(* Logix 5000 AddOnInstructionDefinition export Ed25519_SIGN; software revision 30.00; part 3 of 6 *)

ADD_ON_INSTRUCTION POINT_ENC   (* revision 1.0 20170916, vendor Kenneth A. Fischer *)
// Point Encode:
// Encode point (x,y) values into 32 8-bit pieces
// Requires POINT UDT
// Revision note:
// Rev1.0: 20170916 - Initial Release
VAR_IN_OUT
   Temp_C1 : DINT[22]; {required}
   Temp_C2 : DINT[22]; {required}
   Temp_C3 : DINT[22]; {required}
   Temp_C4 : DINT[22]; {required}   // U
   Temp_D : DINT[43]; {required}
   Temp_E : DINT[32]; {required}
   Inp_P : POINT; {required}
   Out_E : DINT[32]; {required}
END_VAR
VAR_OUTPUT
   i : INT; {access Read Only}
END_VAR
VAR_INPUT
   SEQCTRL_RESET : BOOL;   // Resets Point Multiplication if Toggled True
END_VAR
VAR_OUTPUT
   SEQCTRL_DN : BOOL; {access Read Only}   // Complete
   SEQCTRL_STEP : INT; {access Read Only}
END_VAR
VAR
   SEQCTRL_CMD : INT;
   SEQCTRL_DONE : INT;
   SEQCTRL_CMD_TABLE : INT[40];
   SEQCTRL_NEXT_STEP : INT;
   TEMP : INT;
   j : INT;
   b : DINT;
   B256_MUL : B256_MUL;
   B256_SQU : B256_SQU;
   B256_ADJ : B256_ADJ;
   B256_CtoE : B256_CtoE;
   D_SHL : D_SHL;
   TEMP1 : DINT;
   TEMP2 : DINT;
END_VAR

ROUTINE Logic   (* ladder *)
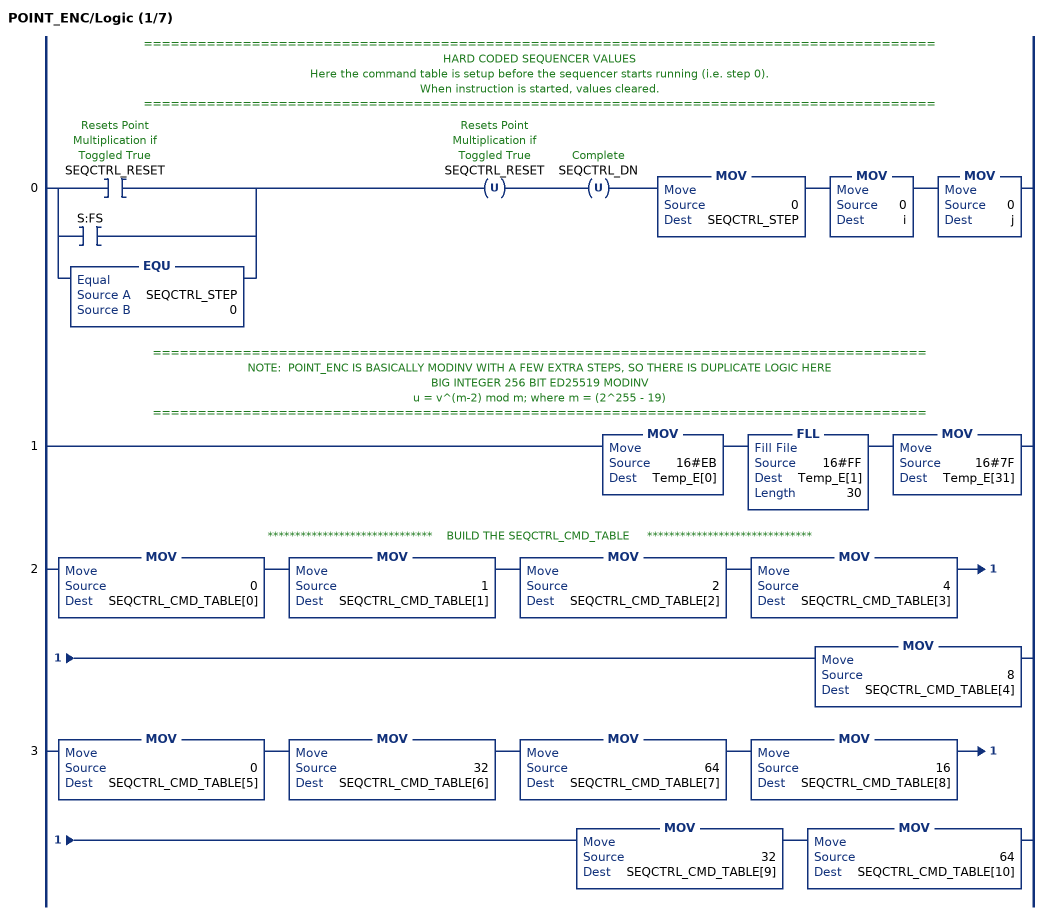
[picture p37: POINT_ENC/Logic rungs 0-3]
   // ========================================================================================
   // HARD CODED SEQUENCER VALUES
   // Here the command table is setup before the sequencer starts running (i.e. step 0).
   // When instruction is started, values cleared.
   // ========================================================================================
   0: [[XIC(SEQCTRL_RESET) ,XIC(S:FS) ] ,EQU(SEQCTRL_STEP,0) ]OTU(SEQCTRL_RESET)OTU(SEQCTRL_DN)MOV(0,SEQCTRL_STEP)MOV(0,i)MOV(0,j);
   // ======================================================================================
   // NOTE:  POINT_ENC IS BASICALLY MODINV WITH A FEW EXTRA STEPS, SO THERE IS DUPLICATE LOGIC HERE
   // BIG INTEGER 256 BIT ED25519 MODINV
   //  u = v^(m-2) mod m; where m = (2^255 - 19)
   // ======================================================================================
   1: MOV(16#EB,Temp_E[0])FLL(16#FF,Temp_E[1],30)MOV(16#7F,Temp_E[31]);
   // ******************************    BUILD THE SEQCTRL_CMD_TABLE     ******************************
   2: MOV(0,SEQCTRL_CMD_TABLE[0])MOV(1,SEQCTRL_CMD_TABLE[1])MOV(2,SEQCTRL_CMD_TABLE[2])MOV(4,SEQCTRL_CMD_TABLE[3])MOV(8,SEQCTRL_CMD_TABLE[4]);
   3: MOV(0,SEQCTRL_CMD_TABLE[5])MOV(32,SEQCTRL_CMD_TABLE[6])MOV(64,SEQCTRL_CMD_TABLE[7])MOV(16,SEQCTRL_CMD_TABLE[8])MOV(32,SEQCTRL_CMD_TABLE[9])MOV(64,SEQCTRL_CMD_TABLE[10]);
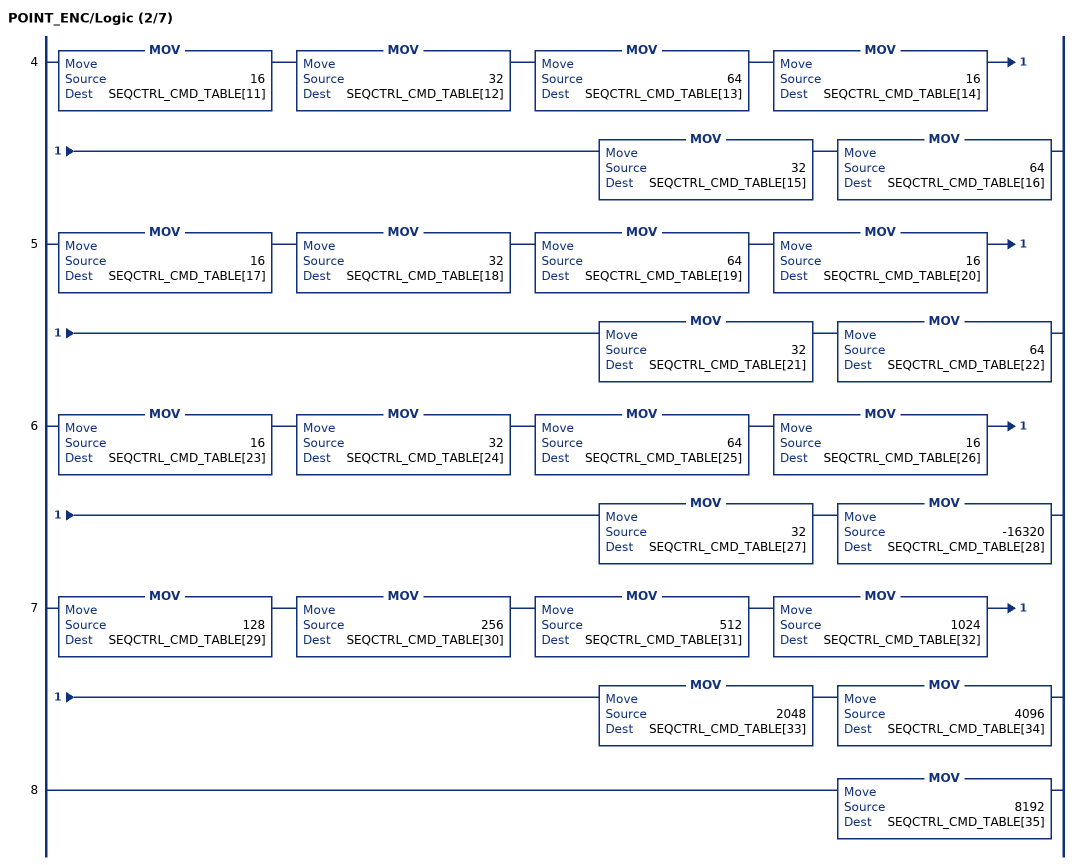
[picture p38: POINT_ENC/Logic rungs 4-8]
   4: MOV(16,SEQCTRL_CMD_TABLE[11])MOV(32,SEQCTRL_CMD_TABLE[12])MOV(64,SEQCTRL_CMD_TABLE[13])MOV(16,SEQCTRL_CMD_TABLE[14])MOV(32,SEQCTRL_CMD_TABLE[15])MOV(64,SEQCTRL_CMD_TABLE[16]);
   5: MOV(16,SEQCTRL_CMD_TABLE[17])MOV(32,SEQCTRL_CMD_TABLE[18])MOV(64,SEQCTRL_CMD_TABLE[19])MOV(16,SEQCTRL_CMD_TABLE[20])MOV(32,SEQCTRL_CMD_TABLE[21])MOV(64,SEQCTRL_CMD_TABLE[22]);
   6: MOV(16,SEQCTRL_CMD_TABLE[23])MOV(32,SEQCTRL_CMD_TABLE[24])MOV(64,SEQCTRL_CMD_TABLE[25])MOV(16,SEQCTRL_CMD_TABLE[26])MOV(32,SEQCTRL_CMD_TABLE[27])MOV(-16320,SEQCTRL_CMD_TABLE[28]);
   7: MOV(128,SEQCTRL_CMD_TABLE[29])MOV(256,SEQCTRL_CMD_TABLE[30])MOV(512,SEQCTRL_CMD_TABLE[31])MOV(1024,SEQCTRL_CMD_TABLE[32])MOV(2048,SEQCTRL_CMD_TABLE[33])MOV(4096,SEQCTRL_CMD_TABLE[34]);
   8: MOV(8192,SEQCTRL_CMD_TABLE[35]);
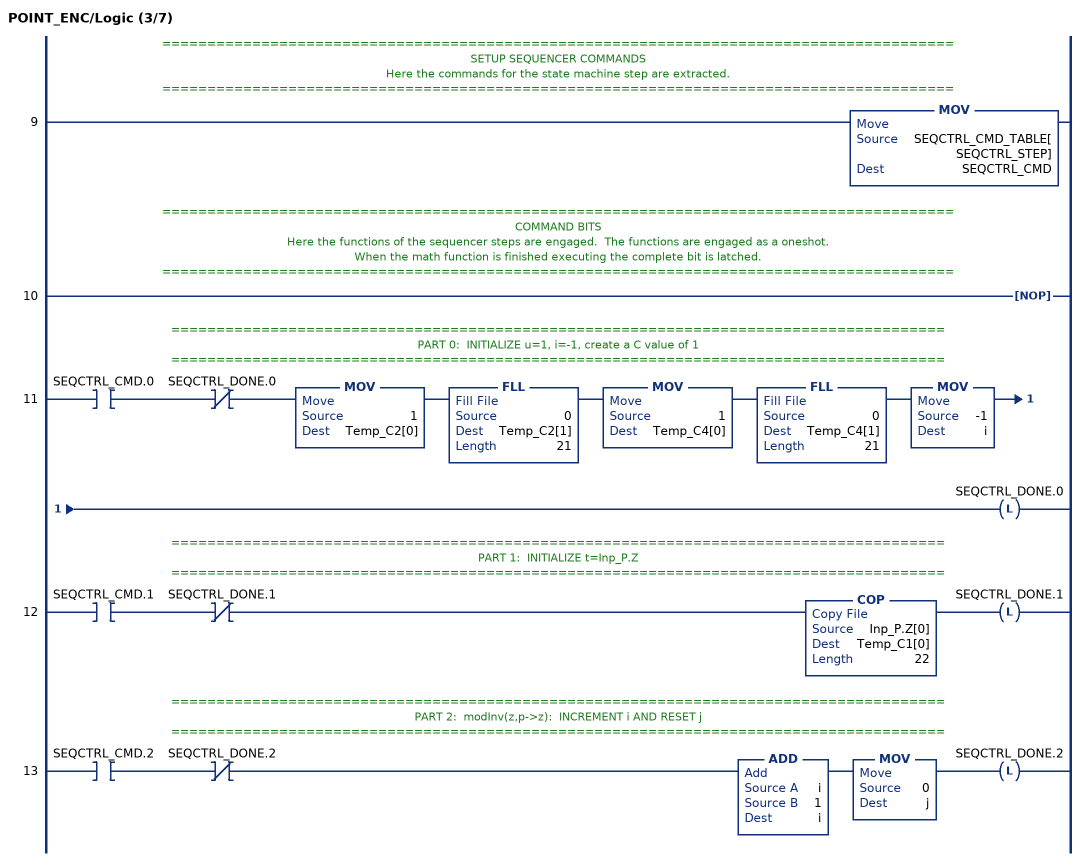
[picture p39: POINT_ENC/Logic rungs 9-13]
   // ========================================================================================
   // SETUP SEQUENCER COMMANDS
   // Here the commands for the state machine step are extracted.
   // ========================================================================================
   9: MOV(SEQCTRL_CMD_TABLE[SEQCTRL_STEP],SEQCTRL_CMD);
   // ========================================================================================
   // COMMAND BITS
   // Here the functions of the sequencer steps are engaged.  The functions are engaged as a oneshot.
   // When the math function is finished executing the complete bit is latched.
   // ========================================================================================
   10: NOP();
   // ======================================================================================
   // PART 0:  INITIALIZE u=1, i=-1, create a C value of 1
   // ======================================================================================
   11: XIC(SEQCTRL_CMD.0)XIO(SEQCTRL_DONE.0)MOV(1,Temp_C2[0])FLL(0,Temp_C2[1],21)MOV(1,Temp_C4[0])FLL(0,Temp_C4[1],21)MOV(-1,i)OTL(SEQCTRL_DONE.0);
   // ======================================================================================
   // PART 1:  INITIALIZE t=Inp_P.Z
   // ======================================================================================
   12: XIC(SEQCTRL_CMD.1)XIO(SEQCTRL_DONE.1)COP(Inp_P.Z[0],Temp_C1[0],22)OTL(SEQCTRL_DONE.1);
   // ======================================================================================
   // PART 2:  modInv(z,p->z):  INCREMENT i AND RESET j
   // ======================================================================================
   13: XIC(SEQCTRL_CMD.2)XIO(SEQCTRL_DONE.2)ADD(i,1,i)MOV(0,j)OTL(SEQCTRL_DONE.2);
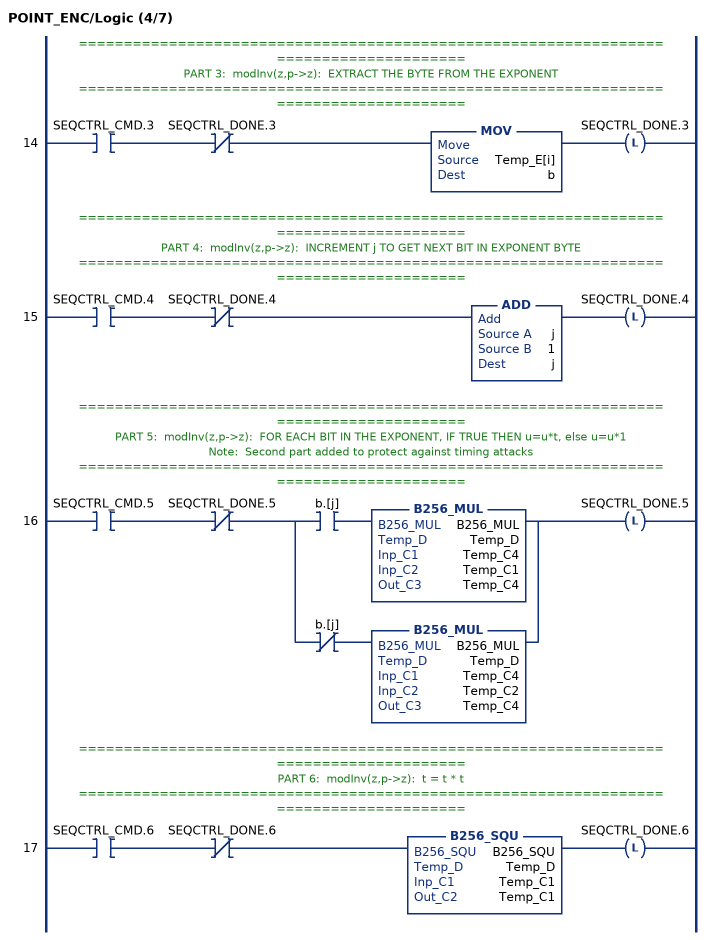
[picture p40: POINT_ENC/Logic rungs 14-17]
   // ======================================================================================
   // PART 3:  modInv(z,p->z):  EXTRACT THE BYTE FROM THE EXPONENT
   // ======================================================================================
   14: XIC(SEQCTRL_CMD.3)XIO(SEQCTRL_DONE.3)MOV(Temp_E[i],b)OTL(SEQCTRL_DONE.3);
   // ======================================================================================
   // PART 4:  modInv(z,p->z):  INCREMENT j TO GET NEXT BIT IN EXPONENT BYTE
   // ======================================================================================
   15: XIC(SEQCTRL_CMD.4)XIO(SEQCTRL_DONE.4)ADD(j,1,j)OTL(SEQCTRL_DONE.4);
   // ======================================================================================
   // PART 5:  modInv(z,p->z):  FOR EACH BIT IN THE EXPONENT, IF TRUE THEN u=u*t, else u=u*1
   // Note:  Second part added to protect against timing attacks
   // ======================================================================================
   16: XIC(SEQCTRL_CMD.5)XIO(SEQCTRL_DONE.5)[XIC(b.[j]) B256_MUL(B256_MUL,Temp_D,Temp_C4,Temp_C1,Temp_C4) ,XIO(b.[j]) B256_MUL(B256_MUL,Temp_D,Temp_C4,Temp_C2,Temp_C4) ]OTL(SEQCTRL_DONE.5);
   // ======================================================================================
   // PART 6:  modInv(z,p->z):  t = t * t
   // ======================================================================================
   17: XIC(SEQCTRL_CMD.6)XIO(SEQCTRL_DONE.6)B256_SQU(B256_SQU,Temp_D,Temp_C1,Temp_C1)OTL(SEQCTRL_DONE.6);
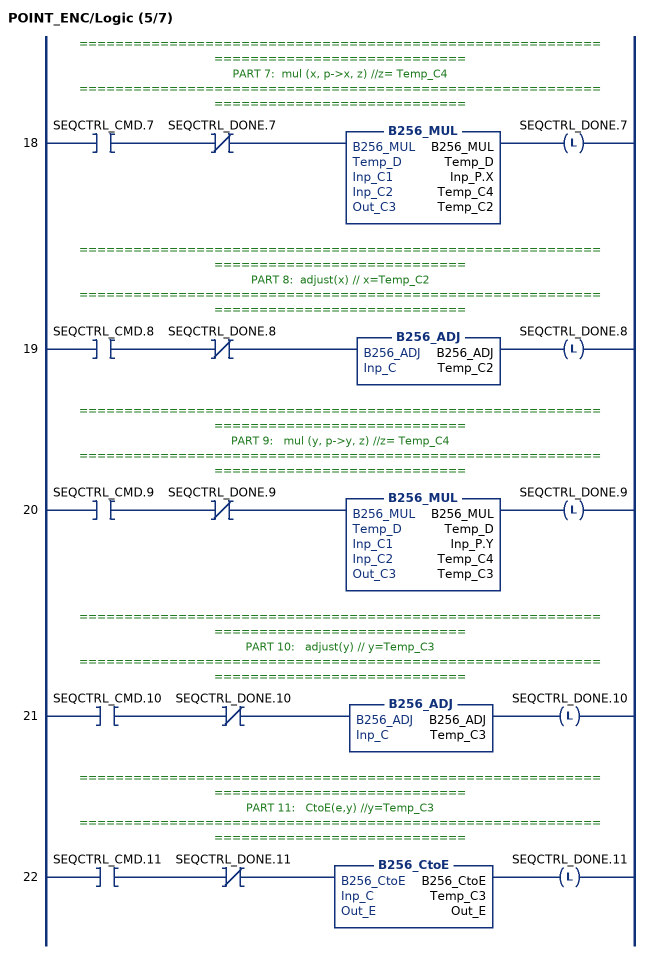
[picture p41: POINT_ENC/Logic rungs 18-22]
   // ======================================================================================
   // PART 7:  mul (x, p->x, z) //z= Temp_C4
   // ======================================================================================
   18: XIC(SEQCTRL_CMD.7)XIO(SEQCTRL_DONE.7)B256_MUL(B256_MUL,Temp_D,Inp_P.X,Temp_C4,Temp_C2)OTL(SEQCTRL_DONE.7);
   // ======================================================================================
   // PART 8:  adjust(x) // x=Temp_C2
   // ======================================================================================
   19: XIC(SEQCTRL_CMD.8)XIO(SEQCTRL_DONE.8)B256_ADJ(B256_ADJ,Temp_C2)OTL(SEQCTRL_DONE.8);
   // ======================================================================================
   // PART 9:   mul (y, p->y, z) //z= Temp_C4
   // ======================================================================================
   20: XIC(SEQCTRL_CMD.9)XIO(SEQCTRL_DONE.9)B256_MUL(B256_MUL,Temp_D,Inp_P.Y,Temp_C4,Temp_C3)OTL(SEQCTRL_DONE.9);
   // ======================================================================================
   // PART 10:   adjust(y) // y=Temp_C3
   // ======================================================================================
   21: XIC(SEQCTRL_CMD.10)XIO(SEQCTRL_DONE.10)B256_ADJ(B256_ADJ,Temp_C3)OTL(SEQCTRL_DONE.10);
   // ======================================================================================
   // PART 11:   CtoE(e,y) //y=Temp_C3
   // ======================================================================================
   22: XIC(SEQCTRL_CMD.11)XIO(SEQCTRL_DONE.11)B256_CtoE(B256_CtoE,Temp_C3,Out_E)OTL(SEQCTRL_DONE.11);
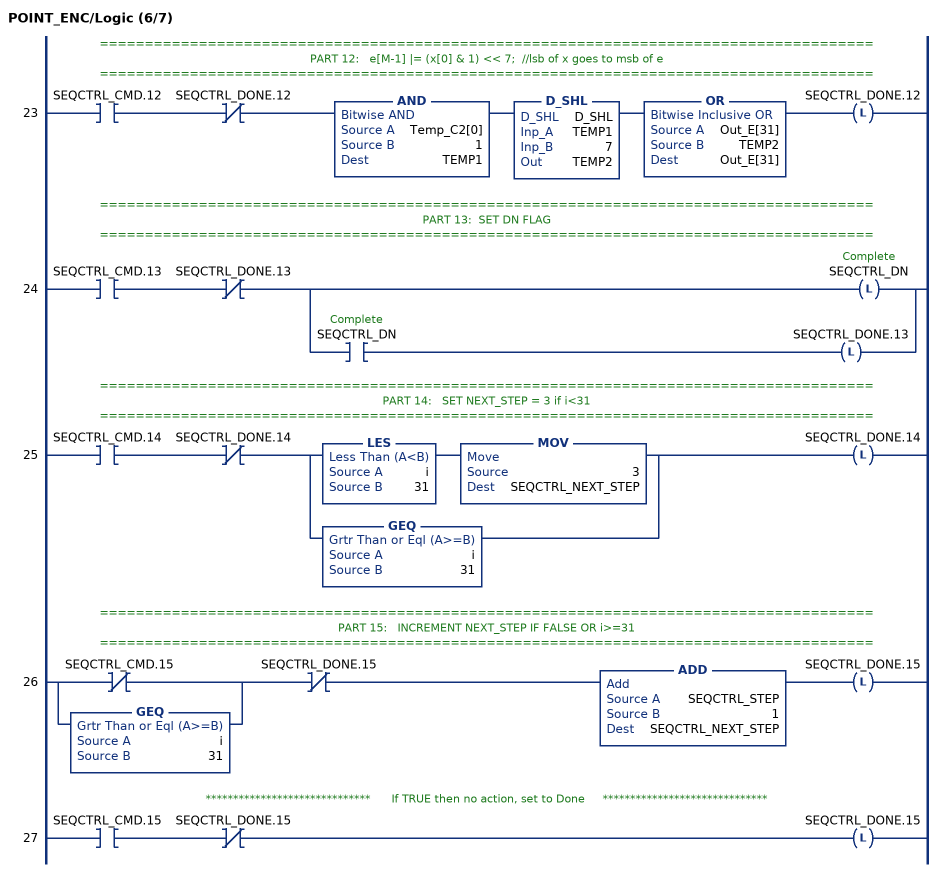
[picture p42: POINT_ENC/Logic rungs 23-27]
   // ======================================================================================
   // PART 12:   e[M-1] |= (x[0] & 1) << 7;  //lsb of x goes to msb of e
   // ======================================================================================
   23: XIC(SEQCTRL_CMD.12)XIO(SEQCTRL_DONE.12)AND(Temp_C2[0],1,TEMP1)D_SHL(D_SHL,TEMP1,7,TEMP2)OR(Out_E[31],TEMP2,Out_E[31])OTL(SEQCTRL_DONE.12);
   // ======================================================================================
   // PART 13:  SET DN FLAG
   // ======================================================================================
   24: XIC(SEQCTRL_CMD.13)XIO(SEQCTRL_DONE.13)[OTL(SEQCTRL_DN) ,XIC(SEQCTRL_DN) OTL(SEQCTRL_DONE.13) ];
   // ======================================================================================
   // PART 14:   SET NEXT_STEP = 3 if i<31
   // ======================================================================================
   25: XIC(SEQCTRL_CMD.14)XIO(SEQCTRL_DONE.14)[LES(i,31) MOV(3,SEQCTRL_NEXT_STEP) ,GEQ(i,31) ]OTL(SEQCTRL_DONE.14);
   // ======================================================================================
   // PART 15:   INCREMENT NEXT_STEP IF FALSE OR i>=31
   // ======================================================================================
   26: [XIO(SEQCTRL_CMD.15) ,GEQ(i,31) ]XIO(SEQCTRL_DONE.15)ADD(SEQCTRL_STEP,1,SEQCTRL_NEXT_STEP)OTL(SEQCTRL_DONE.15);
   // ******************************      If TRUE then no action, set to Done     ******************************
   27: XIC(SEQCTRL_CMD.15)XIO(SEQCTRL_DONE.15)OTL(SEQCTRL_DONE.15);
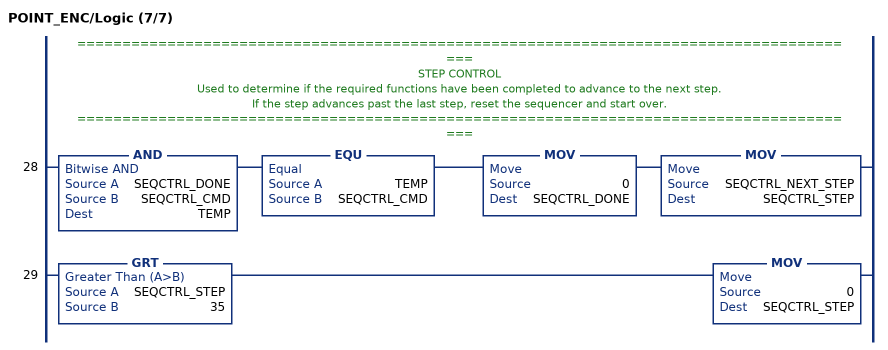
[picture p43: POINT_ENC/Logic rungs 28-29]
   // ========================================================================================
   // STEP CONTROL
   // Used to determine if the required functions have been completed to advance to the next step.
   // If the step advances past the last step, reset the sequencer and start over.
   // ========================================================================================
   28: AND(SEQCTRL_DONE,SEQCTRL_CMD,TEMP)EQU(TEMP,SEQCTRL_CMD)MOV(0,SEQCTRL_DONE)MOV(SEQCTRL_NEXT_STEP,SEQCTRL_STEP);
   29: GRT(SEQCTRL_STEP,35)MOV(0,SEQCTRL_STEP);
END_ROUTINE
END_ADD_ON_INSTRUCTION

ADD_ON_INSTRUCTION B256_MODL   (* revision 1.0 20170916, vendor Kenneth A. Fischer *)
// e = d mod L
// L is curve group order
// Revision note:
// Rev1.0: 20170916 - Initial Release
VAR_IN_OUT
   Temp_C : DINT[22]; {required}
   Temp_D : DINT[43]; {required}
   Inp_D : DINT[43]; {required}   // V
   Out_E : DINT[32]; {required}   // U
END_VAR
VAR_INPUT
   SEQCTRL_RESET : BOOL;   // Resets Mod_L if Toggled True
END_VAR
VAR_OUTPUT
   SEQCTRL_DN : BOOL; {access Read Only}   // Complete
   SEQCTRL_STEP : INT; {access Read Only}
   i : INT; {access Read Only}
END_VAR
VAR
   SEQCTRL_CMD : INT;
   SEQCTRL_DONE : INT;
   SEQCTRL_NEXT_STEP : INT;
   j : INT;
   SEQCTRL_CMD_TABLE : INT[100];
   k : INT;
   p : INT;
   t : DINT;
   carry : DINT;
   s : DINT;
   q : INT;
   TEMP : INT;
   L : DINT[22];
   TEMPDINT : DINT;
   D_SHR : D_SHR;
   negative : DINT;
   B256_CtoE : B256_CtoE;
END_VAR

ROUTINE Logic   (* ladder *)
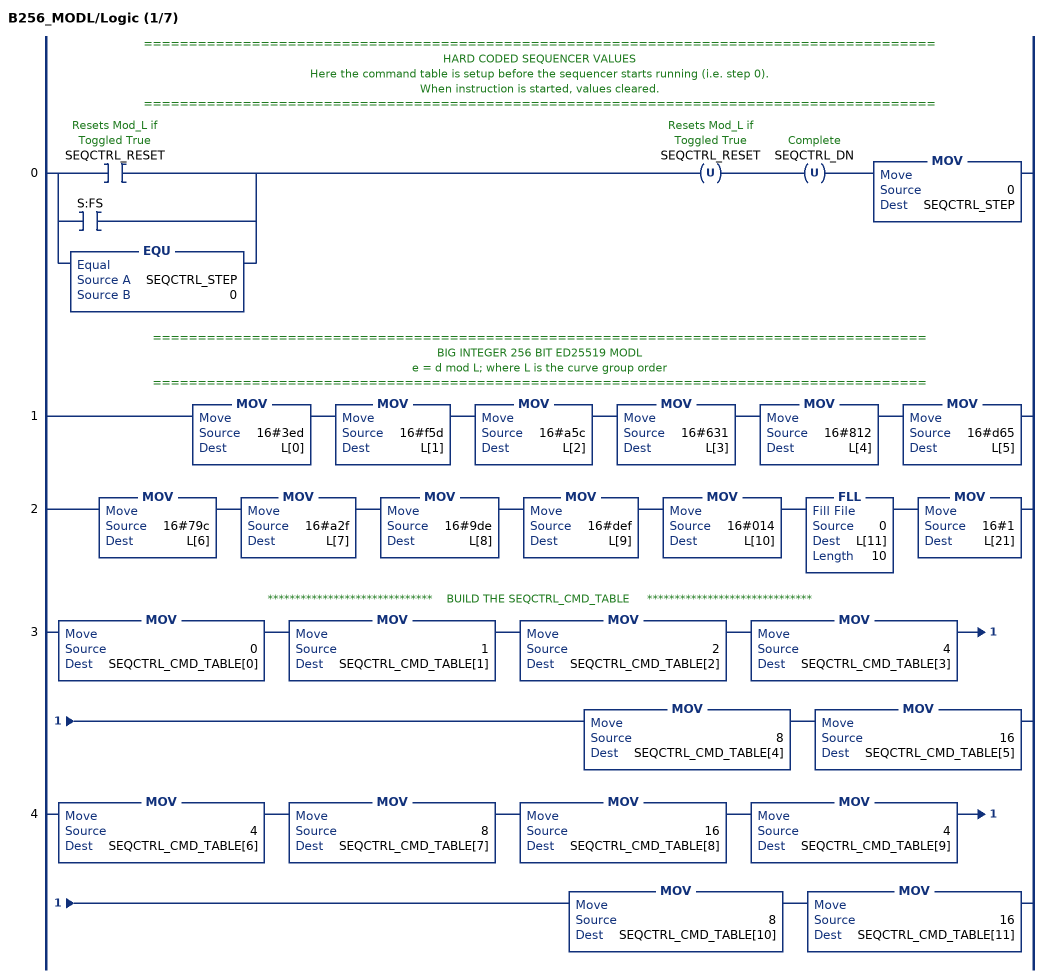
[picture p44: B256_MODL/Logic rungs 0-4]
   // ========================================================================================
   // HARD CODED SEQUENCER VALUES
   // Here the command table is setup before the sequencer starts running (i.e. step 0).
   // When instruction is started, values cleared.
   // ========================================================================================
   0: [[XIC(SEQCTRL_RESET) ,XIC(S:FS) ] ,EQU(SEQCTRL_STEP,0) ]OTU(SEQCTRL_RESET)OTU(SEQCTRL_DN)MOV(0,SEQCTRL_STEP);
   // ======================================================================================
   // BIG INTEGER 256 BIT ED25519 MODL
   //  e = d mod L; where L is the curve group order
   // ======================================================================================
   1: MOV(16#3ed,L[0])MOV(16#f5d,L[1])MOV(16#a5c,L[2])MOV(16#631,L[3])MOV(16#812,L[4])MOV(16#d65,L[5]);
   2: MOV(16#79c,L[6])MOV(16#a2f,L[7])MOV(16#9de,L[8])MOV(16#def,L[9])MOV(16#014,L[10])FLL(0,L[11],10)MOV(16#1,L[21]);
   // ******************************    BUILD THE SEQCTRL_CMD_TABLE     ******************************
   3: MOV(0,SEQCTRL_CMD_TABLE[0])MOV(1,SEQCTRL_CMD_TABLE[1])MOV(2,SEQCTRL_CMD_TABLE[2])MOV(4,SEQCTRL_CMD_TABLE[3])MOV(8,SEQCTRL_CMD_TABLE[4])MOV(16,SEQCTRL_CMD_TABLE[5]);
   4: MOV(4,SEQCTRL_CMD_TABLE[6])MOV(8,SEQCTRL_CMD_TABLE[7])MOV(16,SEQCTRL_CMD_TABLE[8])MOV(4,SEQCTRL_CMD_TABLE[9])MOV(8,SEQCTRL_CMD_TABLE[10])MOV(16,SEQCTRL_CMD_TABLE[11]);
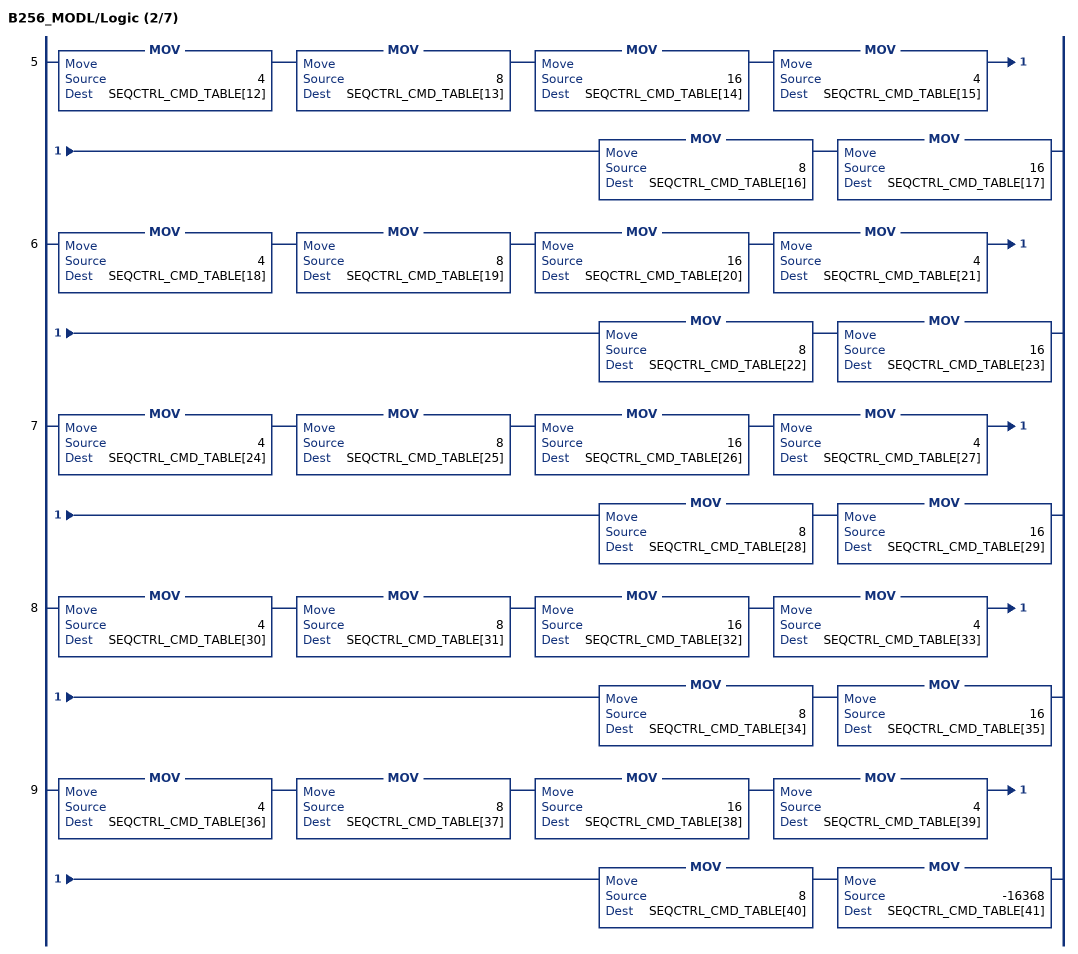
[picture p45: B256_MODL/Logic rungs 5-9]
   5: MOV(4,SEQCTRL_CMD_TABLE[12])MOV(8,SEQCTRL_CMD_TABLE[13])MOV(16,SEQCTRL_CMD_TABLE[14])MOV(4,SEQCTRL_CMD_TABLE[15])MOV(8,SEQCTRL_CMD_TABLE[16])MOV(16,SEQCTRL_CMD_TABLE[17]);
   6: MOV(4,SEQCTRL_CMD_TABLE[18])MOV(8,SEQCTRL_CMD_TABLE[19])MOV(16,SEQCTRL_CMD_TABLE[20])MOV(4,SEQCTRL_CMD_TABLE[21])MOV(8,SEQCTRL_CMD_TABLE[22])MOV(16,SEQCTRL_CMD_TABLE[23]);
   7: MOV(4,SEQCTRL_CMD_TABLE[24])MOV(8,SEQCTRL_CMD_TABLE[25])MOV(16,SEQCTRL_CMD_TABLE[26])MOV(4,SEQCTRL_CMD_TABLE[27])MOV(8,SEQCTRL_CMD_TABLE[28])MOV(16,SEQCTRL_CMD_TABLE[29]);
   8: MOV(4,SEQCTRL_CMD_TABLE[30])MOV(8,SEQCTRL_CMD_TABLE[31])MOV(16,SEQCTRL_CMD_TABLE[32])MOV(4,SEQCTRL_CMD_TABLE[33])MOV(8,SEQCTRL_CMD_TABLE[34])MOV(16,SEQCTRL_CMD_TABLE[35]);
   9: MOV(4,SEQCTRL_CMD_TABLE[36])MOV(8,SEQCTRL_CMD_TABLE[37])MOV(16,SEQCTRL_CMD_TABLE[38])MOV(4,SEQCTRL_CMD_TABLE[39])MOV(8,SEQCTRL_CMD_TABLE[40])MOV(-16368,SEQCTRL_CMD_TABLE[41]);
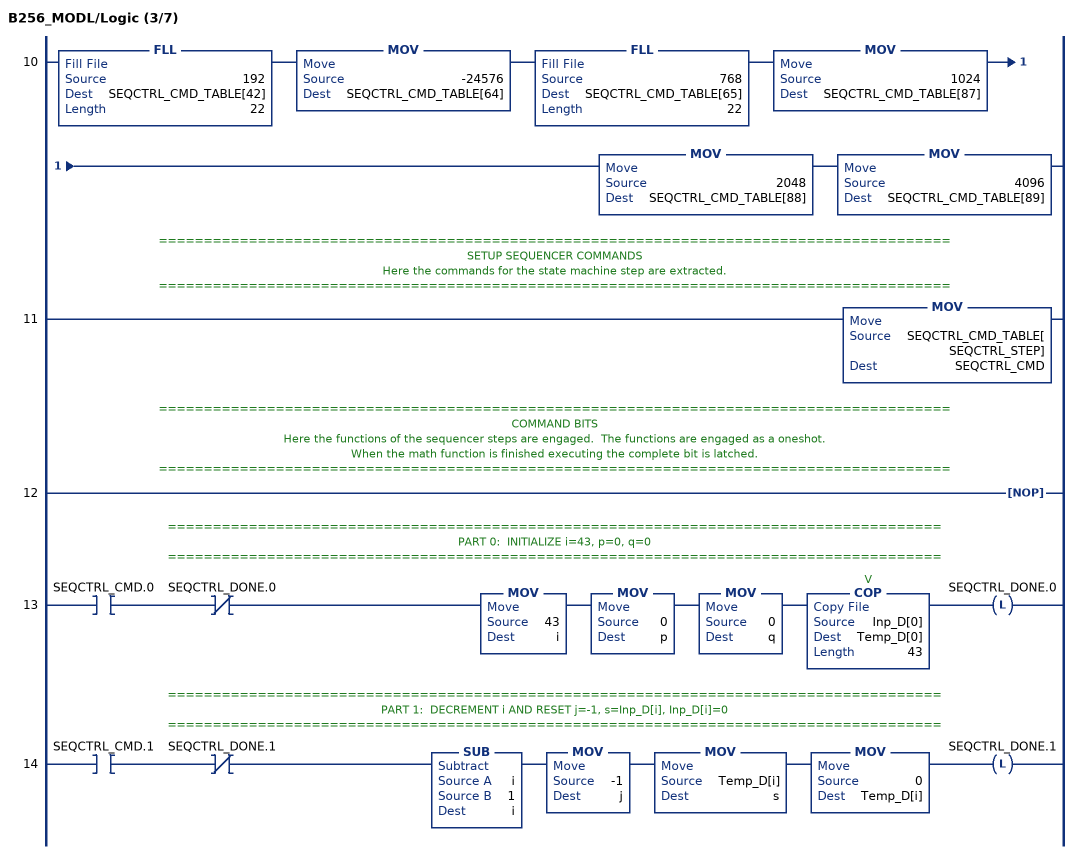
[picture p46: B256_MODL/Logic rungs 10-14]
   10: FLL(192,SEQCTRL_CMD_TABLE[42],22)MOV(-24576,SEQCTRL_CMD_TABLE[64])FLL(768,SEQCTRL_CMD_TABLE[65],22)MOV(1024,SEQCTRL_CMD_TABLE[87])MOV(2048,SEQCTRL_CMD_TABLE[88])MOV(4096,SEQCTRL_CMD_TABLE[89]);
   // ========================================================================================
   // SETUP SEQUENCER COMMANDS
   // Here the commands for the state machine step are extracted.
   // ========================================================================================
   11: MOV(SEQCTRL_CMD_TABLE[SEQCTRL_STEP],SEQCTRL_CMD);
   // ========================================================================================
   // COMMAND BITS
   // Here the functions of the sequencer steps are engaged.  The functions are engaged as a oneshot.
   // When the math function is finished executing the complete bit is latched.
   // ========================================================================================
   12: NOP();
   // ======================================================================================
   // PART 0:  INITIALIZE i=43, p=0, q=0
   // ======================================================================================
   13: XIC(SEQCTRL_CMD.0)XIO(SEQCTRL_DONE.0)MOV(43,i)MOV(0,p)MOV(0,q)COP(Inp_D[0],Temp_D[0],43)OTL(SEQCTRL_DONE.0);
   // ======================================================================================
   // PART 1:  DECREMENT i AND RESET j=-1, s=Inp_D[i], Inp_D[i]=0
   // ======================================================================================
   14: XIC(SEQCTRL_CMD.1)XIO(SEQCTRL_DONE.1)SUB(i,1,i)MOV(-1,j)MOV(Temp_D[i],s)MOV(0,Temp_D[i])OTL(SEQCTRL_DONE.1);
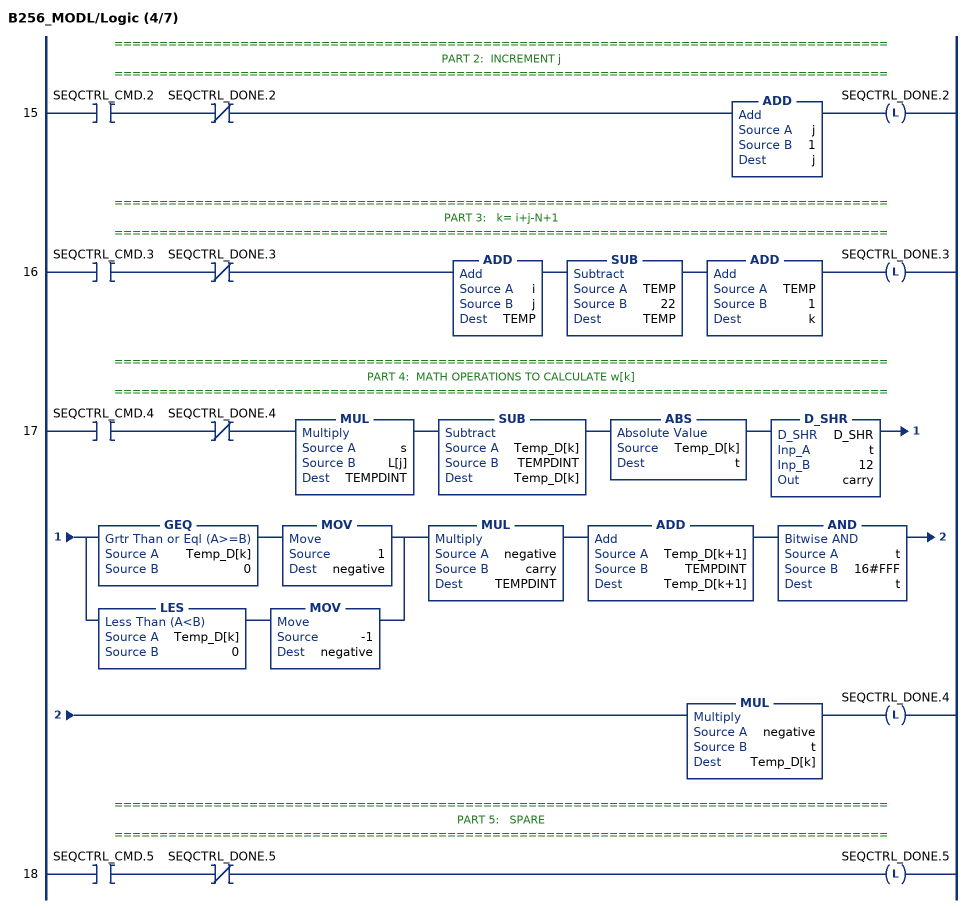
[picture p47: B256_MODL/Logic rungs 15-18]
   // ======================================================================================
   // PART 2:  INCREMENT j
   // ======================================================================================
   15: XIC(SEQCTRL_CMD.2)XIO(SEQCTRL_DONE.2)ADD(j,1,j)OTL(SEQCTRL_DONE.2);
   // ======================================================================================
   // PART 3:   k= i+j-N+1
   // ======================================================================================
   16: XIC(SEQCTRL_CMD.3)XIO(SEQCTRL_DONE.3)ADD(i,j,TEMP)SUB(TEMP,22,TEMP)ADD(TEMP,1,k)OTL(SEQCTRL_DONE.3);
   // ======================================================================================
   // PART 4:  MATH OPERATIONS TO CALCULATE w[k]
   // ======================================================================================
   17: XIC(SEQCTRL_CMD.4)XIO(SEQCTRL_DONE.4)MUL(s,L[j],TEMPDINT)SUB(Temp_D[k],TEMPDINT,Temp_D[k])ABS(Temp_D[k],t)D_SHR(D_SHR,t,12,carry)[GEQ(Temp_D[k],0) MOV(1,negative) ,LES(Temp_D[k],0) MOV(-1,negative) ]MUL(negative,carry,TEMPDINT)ADD(Temp_D[k+1],TEMPDINT,Temp_D[k+1])AND(t,16#FFF,t)MUL(negative,t,Temp_D[k])OTL(SEQCTRL_DONE.4);
   // ======================================================================================
   // PART 5:   SPARE
   // ======================================================================================
   18: XIC(SEQCTRL_CMD.5)XIO(SEQCTRL_DONE.5)OTL(SEQCTRL_DONE.5);
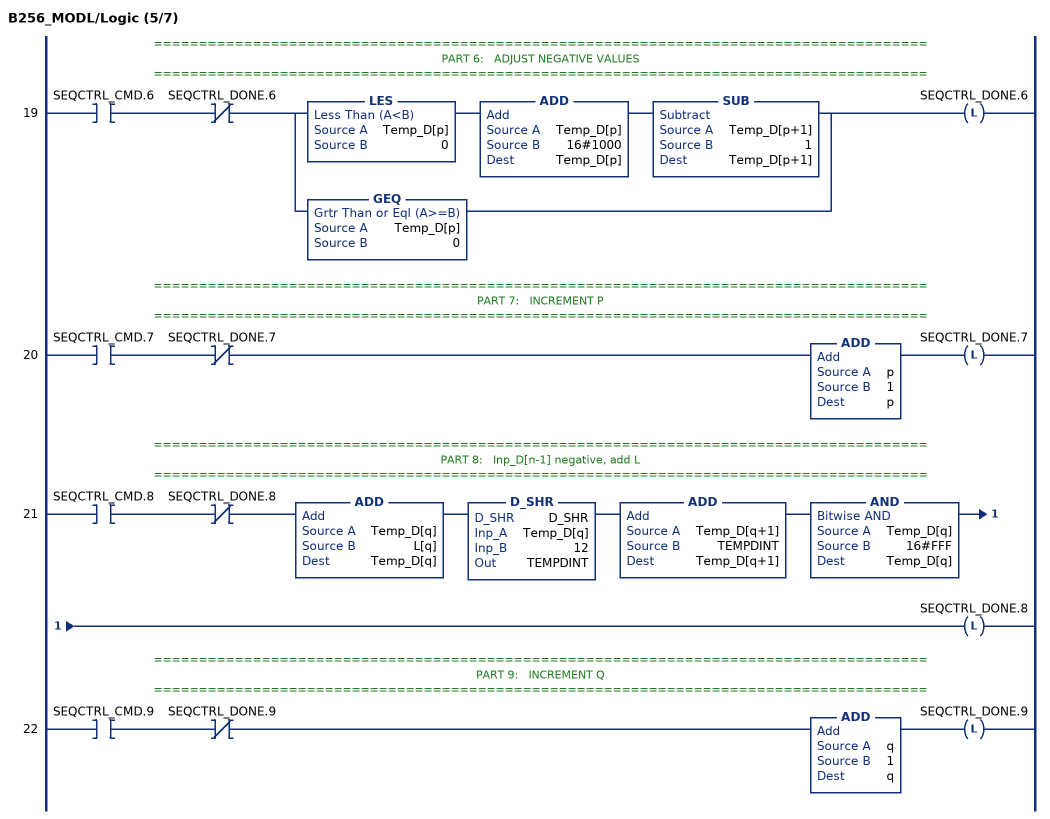
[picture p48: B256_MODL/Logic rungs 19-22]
   // ======================================================================================
   // PART 6:   ADJUST NEGATIVE VALUES
   // ======================================================================================
   19: XIC(SEQCTRL_CMD.6)XIO(SEQCTRL_DONE.6)[LES(Temp_D[p],0) ADD(Temp_D[p],16#1000,Temp_D[p]) SUB(Temp_D[p+1],1,Temp_D[p+1]) ,GEQ(Temp_D[p],0) ]OTL(SEQCTRL_DONE.6);
   // ======================================================================================
   // PART 7:   INCREMENT P
   // ======================================================================================
   20: XIC(SEQCTRL_CMD.7)XIO(SEQCTRL_DONE.7)ADD(p,1,p)OTL(SEQCTRL_DONE.7);
   // ======================================================================================
   // PART 8:   Inp_D[n-1] negative, add L
   // ======================================================================================
   21: XIC(SEQCTRL_CMD.8)XIO(SEQCTRL_DONE.8)ADD(Temp_D[q],L[q],Temp_D[q])D_SHR(D_SHR,Temp_D[q],12,TEMPDINT)ADD(Temp_D[q+1],TEMPDINT,Temp_D[q+1])AND(Temp_D[q],16#FFF,Temp_D[q])OTL(SEQCTRL_DONE.8);
   // ======================================================================================
   // PART 9:   INCREMENT Q
   // ======================================================================================
   22: XIC(SEQCTRL_CMD.9)XIO(SEQCTRL_DONE.9)ADD(q,1,q)OTL(SEQCTRL_DONE.9);
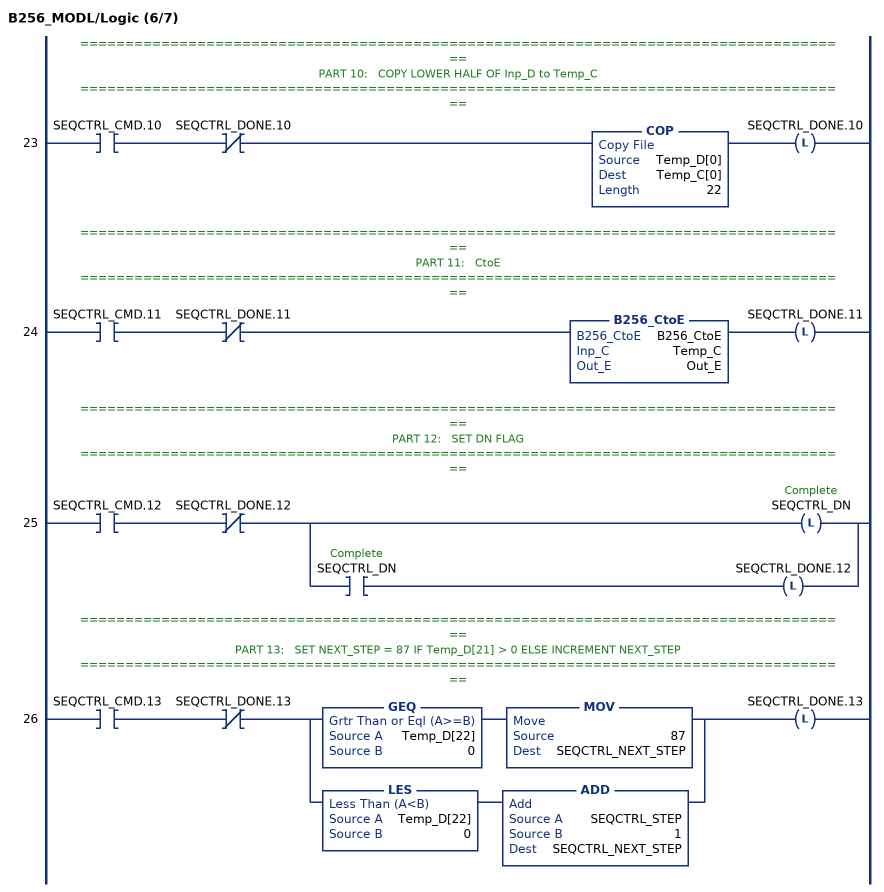
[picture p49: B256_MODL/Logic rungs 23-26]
   // ======================================================================================
   // PART 10:   COPY LOWER HALF OF Inp_D to Temp_C
   // ======================================================================================
   23: XIC(SEQCTRL_CMD.10)XIO(SEQCTRL_DONE.10)COP(Temp_D[0],Temp_C[0],22)OTL(SEQCTRL_DONE.10);
   // ======================================================================================
   // PART 11:   CtoE
   // ======================================================================================
   24: XIC(SEQCTRL_CMD.11)XIO(SEQCTRL_DONE.11)B256_CtoE(B256_CtoE,Temp_C,Out_E)OTL(SEQCTRL_DONE.11);
   // ======================================================================================
   // PART 12:   SET DN FLAG
   // ======================================================================================
   25: XIC(SEQCTRL_CMD.12)XIO(SEQCTRL_DONE.12)[OTL(SEQCTRL_DN) ,XIC(SEQCTRL_DN) OTL(SEQCTRL_DONE.12) ];
   // ======================================================================================
   // PART 13:   SET NEXT_STEP = 87 IF Temp_D[21] > 0 ELSE INCREMENT NEXT_STEP
   // ======================================================================================
   26: XIC(SEQCTRL_CMD.13)XIO(SEQCTRL_DONE.13)[GEQ(Temp_D[22],0) MOV(87,SEQCTRL_NEXT_STEP) ,LES(Temp_D[22],0) ADD(SEQCTRL_STEP,1,SEQCTRL_NEXT_STEP) ]OTL(SEQCTRL_DONE.13);
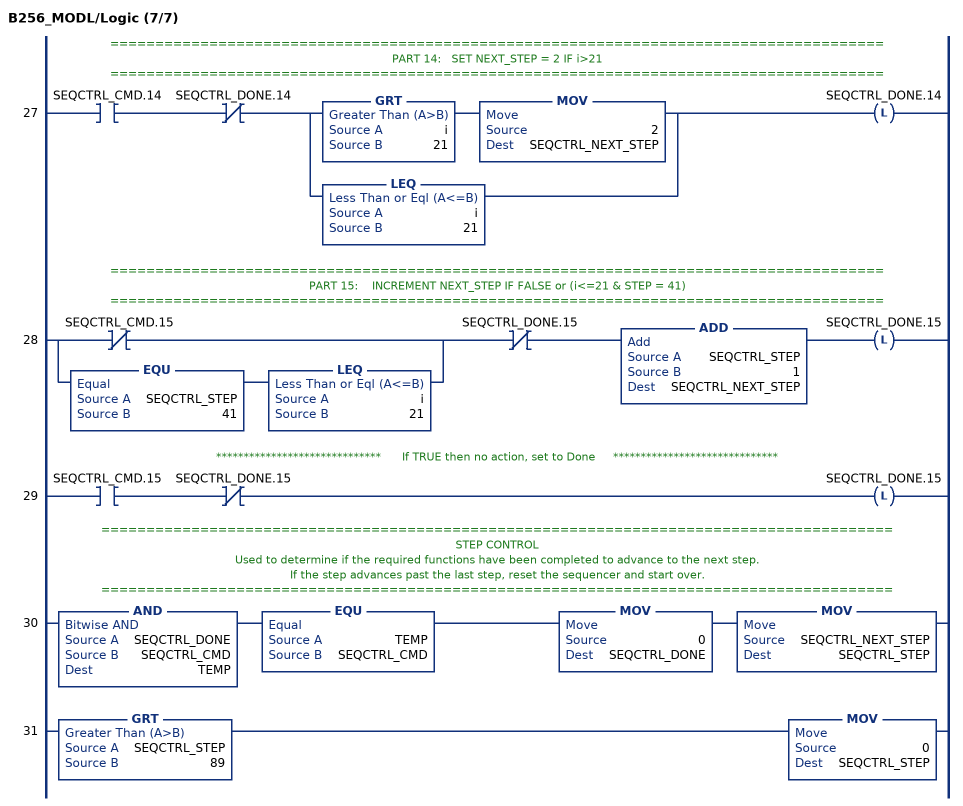
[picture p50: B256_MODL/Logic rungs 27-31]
   // ======================================================================================
   // PART 14:   SET NEXT_STEP = 2 IF i>21
   // ======================================================================================
   27: XIC(SEQCTRL_CMD.14)XIO(SEQCTRL_DONE.14)[GRT(i,21) MOV(2,SEQCTRL_NEXT_STEP) ,LEQ(i,21) ]OTL(SEQCTRL_DONE.14);
   // ======================================================================================
   // PART 15:    INCREMENT NEXT_STEP IF FALSE or (i<=21 & STEP = 41)
   // ======================================================================================
   28: [XIO(SEQCTRL_CMD.15) ,EQU(SEQCTRL_STEP,41) LEQ(i,21) ]XIO(SEQCTRL_DONE.15)ADD(SEQCTRL_STEP,1,SEQCTRL_NEXT_STEP)OTL(SEQCTRL_DONE.15);
   // ******************************      If TRUE then no action, set to Done     ******************************
   29: XIC(SEQCTRL_CMD.15)XIO(SEQCTRL_DONE.15)OTL(SEQCTRL_DONE.15);
   // ========================================================================================
   // STEP CONTROL
   // Used to determine if the required functions have been completed to advance to the next step.
   // If the step advances past the last step, reset the sequencer and start over.
   // ========================================================================================
   30: AND(SEQCTRL_DONE,SEQCTRL_CMD,TEMP)EQU(TEMP,SEQCTRL_CMD)MOV(0,SEQCTRL_DONE)MOV(SEQCTRL_NEXT_STEP,SEQCTRL_STEP);
   31: GRT(SEQCTRL_STEP,89)MOV(0,SEQCTRL_STEP);
END_ROUTINE
END_ADD_ON_INSTRUCTION

ADD_ON_INSTRUCTION B256_CtoS   (* revision 1.0 20170916, vendor Kenneth A. Fischer *)
// Convert 256-bit value using 22 12-bit pieces into 64 hex big endian string characters
// Revision note:
// Rev1.0: 20170916 - Initial Release
VAR_IN_OUT
   Inp_C : DINT[22]; {required}
   Out_S : STRING; {required}
END_VAR
VAR
   byte : DINT[3];
   i : INT;
   j : INT;
   k : DINT;
   D_SHR : D_SHR;
END_VAR

ROUTINE Logic   (* ladder *)
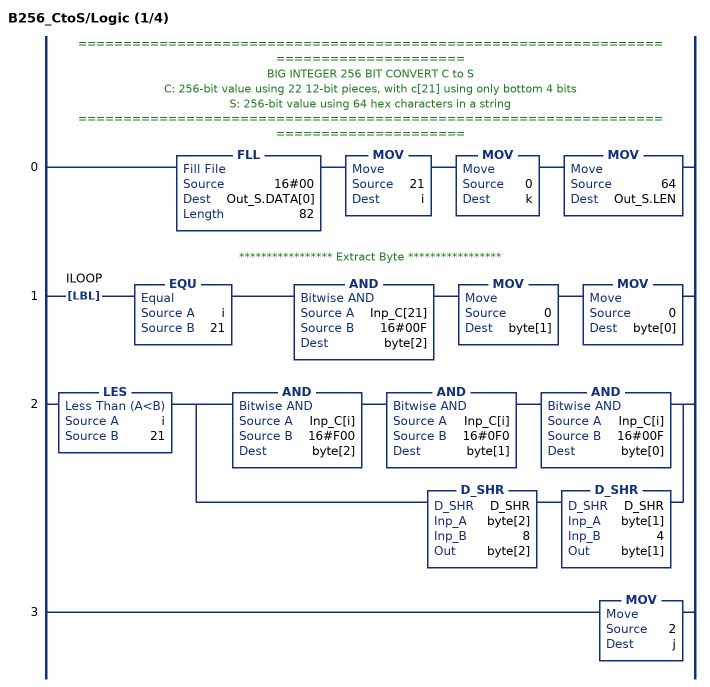
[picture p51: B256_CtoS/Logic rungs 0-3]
   // ======================================================================================
   // BIG INTEGER 256 BIT CONVERT C to S
   // C: 256-bit value using 22 12-bit pieces, with c[21] using only bottom 4 bits
   // S: 256-bit value using 64 hex characters in a string
   // ======================================================================================
   0: FLL(16#00,Out_S.DATA[0],82)MOV(21,i)MOV(0,k)MOV(64,Out_S.LEN);
   // ***************** Extract Byte *****************
   1: LBL(ILOOP)EQU(i,21)AND(Inp_C[21],16#00F,byte[2])MOV(0,byte[1])MOV(0,byte[0]);
   2: LES(i,21)[AND(Inp_C[i],16#F00,byte[2]) AND(Inp_C[i],16#0F0,byte[1]) AND(Inp_C[i],16#00F,byte[0]) ,D_SHR(D_SHR,byte[2],8,byte[2]) D_SHR(D_SHR,byte[1],4,byte[1]) ];
   3: MOV(2,j);
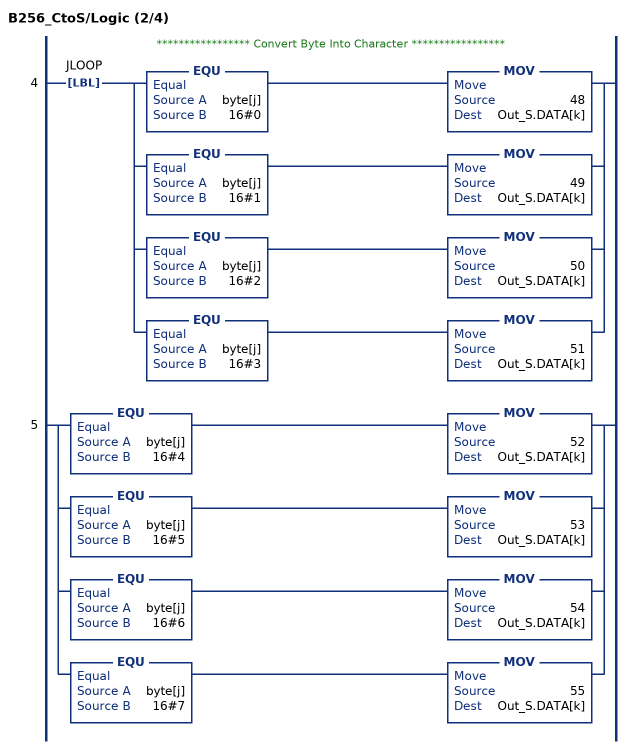
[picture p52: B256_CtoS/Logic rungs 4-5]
   // ***************** Convert Byte Into Character *****************
   4: LBL(JLOOP)[EQU(byte[j],16#0) MOV(48,Out_S.DATA[k]) ,EQU(byte[j],16#1) MOV(49,Out_S.DATA[k]) ,EQU(byte[j],16#2) MOV(50,Out_S.DATA[k]) ,EQU(byte[j],16#3) MOV(51,Out_S.DATA[k]) ];
   5: [EQU(byte[j],16#4) MOV(52,Out_S.DATA[k]) ,EQU(byte[j],16#5) MOV(53,Out_S.DATA[k]) ,EQU(byte[j],16#6) MOV(54,Out_S.DATA[k]) ,EQU(byte[j],16#7) MOV(55,Out_S.DATA[k]) ];
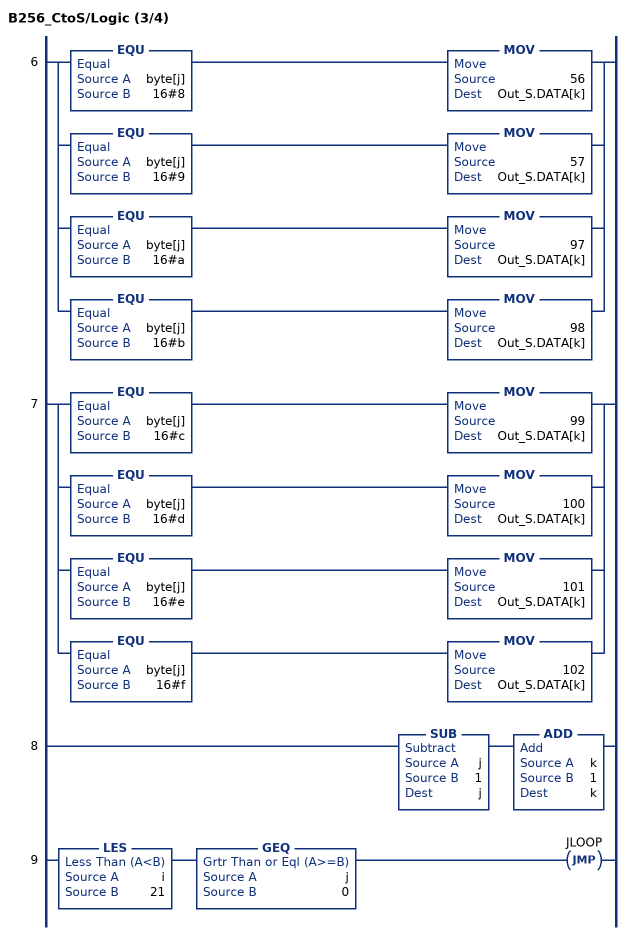
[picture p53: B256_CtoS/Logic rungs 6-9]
   6: [EQU(byte[j],16#8) MOV(56,Out_S.DATA[k]) ,EQU(byte[j],16#9) MOV(57,Out_S.DATA[k]) ,EQU(byte[j],16#a) MOV(97,Out_S.DATA[k]) ,EQU(byte[j],16#b) MOV(98,Out_S.DATA[k]) ];
   7: [EQU(byte[j],16#c) MOV(99,Out_S.DATA[k]) ,EQU(byte[j],16#d) MOV(100,Out_S.DATA[k]) ,EQU(byte[j],16#e) MOV(101,Out_S.DATA[k]) ,EQU(byte[j],16#f) MOV(102,Out_S.DATA[k]) ];
   8: SUB(j,1,j)ADD(k,1,k);
   9: LES(i,21)GEQ(j,0)JMP(JLOOP);
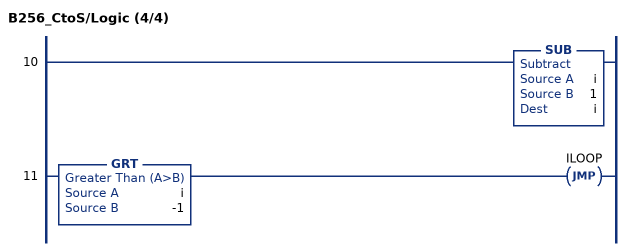
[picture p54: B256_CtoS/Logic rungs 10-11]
   10: SUB(i,1,i);
   11: GRT(i,-1)JMP(ILOOP);
END_ROUTINE
END_ADD_ON_INSTRUCTION
(* Logix 5000 AddOnInstructionDefinition export Ed25519_SIGN; software revision 30.00; part 4 of 6 *)

ADD_ON_INSTRUCTION B256_EtoC   (* revision 1.0 20170916, vendor Kenneth A. Fischer *)
// Convert 256-bit value using 32 8-bit pieces into 256-bit value using 22 12-bit pieces
// Revision note:
// Rev1.0: 20170916 - Initial Release
VAR_IN_OUT
   Inp_E : DINT[32]; {required}
   Out_C : DINT[22]; {required}
END_VAR
VAR
   i : INT;
   j : INT;
   TEMP1 : DINT;
   TEMP2 : DINT;
   D_SHL : D_SHL;
   D_SHR : D_SHR;
END_VAR

ROUTINE Logic   (* ladder *)
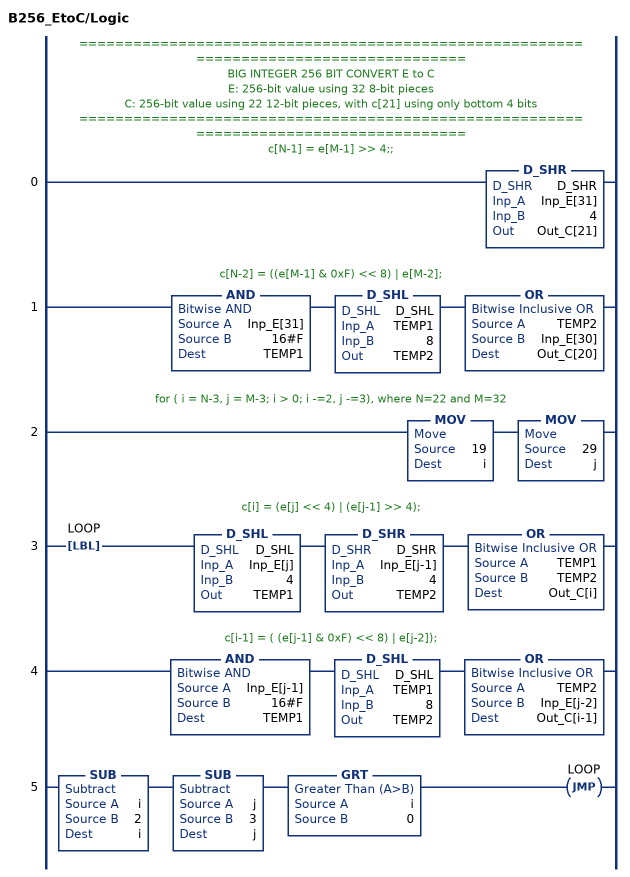
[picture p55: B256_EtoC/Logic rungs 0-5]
   // ======================================================================================
   // BIG INTEGER 256 BIT CONVERT E to C
   // E: 256-bit value using 32 8-bit pieces
   // C: 256-bit value using 22 12-bit pieces, with c[21] using only bottom 4 bits
   // ======================================================================================
   // c[N-1] = e[M-1] >> 4;;
   0: D_SHR(D_SHR,Inp_E[31],4,Out_C[21]);
   // c[N-2] = ((e[M-1] & 0xF) << 8) | e[M-2];
   1: AND(Inp_E[31],16#F,TEMP1)D_SHL(D_SHL,TEMP1,8,TEMP2)OR(TEMP2,Inp_E[30],Out_C[20]);
   // for ( i = N-3, j = M-3; i > 0; i -=2, j -=3), where N=22 and M=32
   2: MOV(19,i)MOV(29,j);
   // c[i] = (e[j] << 4) | (e[j-1] >> 4);
   3: LBL(LOOP)D_SHL(D_SHL,Inp_E[j],4,TEMP1)D_SHR(D_SHR,Inp_E[j-1],4,TEMP2)OR(TEMP1,TEMP2,Out_C[i]);
   // c[i-1] = ( (e[j-1] & 0xF) << 8) | e[j-2]);
   4: AND(Inp_E[j-1],16#F,TEMP1)D_SHL(D_SHL,TEMP1,8,TEMP2)OR(TEMP2,Inp_E[j-2],Out_C[i-1]);
   5: SUB(i,2,i)SUB(j,3,j)GRT(i,0)JMP(LOOP);
END_ROUTINE
END_ADD_ON_INSTRUCTION

ADD_ON_INSTRUCTION B256_EtoL   (* revision 1.0 20170916, vendor Kenneth A. Fischer *)
// Convert 256-bit value using 32 8-bit pieces into 256-bit value using 4 64-bit pieces
// Revision note:
// Rev1.0: 20170916 - Initial Release
VAR_IN_OUT
   Inp_E : DINT[32]; {required}
   Out_L : LINT[4]; {required}
END_VAR
VAR
   D_SHL : D_SHL;
   Wrk_Out : DINT[2];
   i : INT;
   j : INT;
   TEMP : DINT;
END_VAR

ROUTINE Logic   (* ladder *)
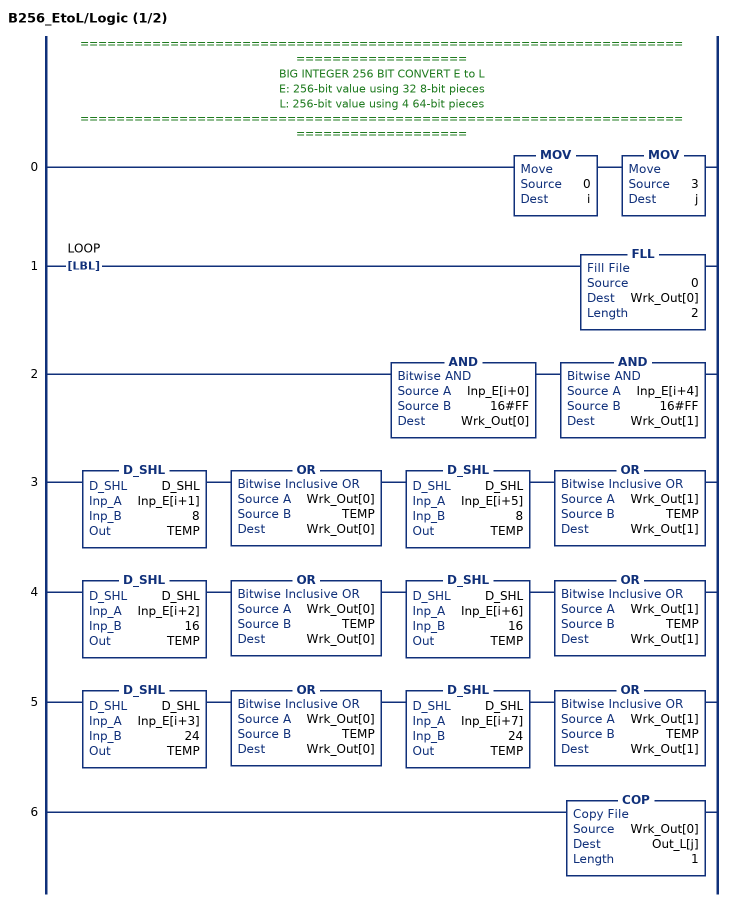
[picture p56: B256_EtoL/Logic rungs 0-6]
   // ======================================================================================
   // BIG INTEGER 256 BIT CONVERT E to L
   // E: 256-bit value using 32 8-bit pieces
   // L: 256-bit value using 4 64-bit pieces
   // ======================================================================================
   0: MOV(0,i)MOV(3,j);
   1: LBL(LOOP)FLL(0,Wrk_Out[0],2);
   2: AND(Inp_E[i+0],16#FF,Wrk_Out[0])AND(Inp_E[i+4],16#FF,Wrk_Out[1]);
   3: D_SHL(D_SHL,Inp_E[i+1],8,TEMP)OR(Wrk_Out[0],TEMP,Wrk_Out[0])D_SHL(D_SHL,Inp_E[i+5],8,TEMP)OR(Wrk_Out[1],TEMP,Wrk_Out[1]);
   4: D_SHL(D_SHL,Inp_E[i+2],16,TEMP)OR(Wrk_Out[0],TEMP,Wrk_Out[0])D_SHL(D_SHL,Inp_E[i+6],16,TEMP)OR(Wrk_Out[1],TEMP,Wrk_Out[1]);
   5: D_SHL(D_SHL,Inp_E[i+3],24,TEMP)OR(Wrk_Out[0],TEMP,Wrk_Out[0])D_SHL(D_SHL,Inp_E[i+7],24,TEMP)OR(Wrk_Out[1],TEMP,Wrk_Out[1]);
   6: COP(Wrk_Out[0],Out_L[j],1);
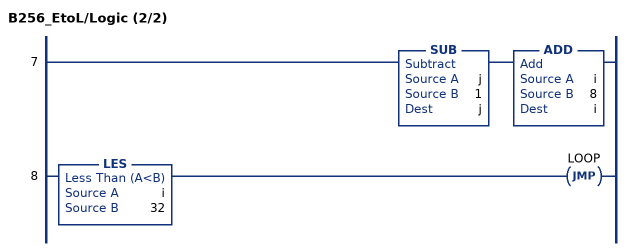
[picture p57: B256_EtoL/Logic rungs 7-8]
   7: SUB(j,1,j)ADD(i,8,i);
   8: LES(i,32)JMP(LOOP);
END_ROUTINE
END_ADD_ON_INSTRUCTION

ADD_ON_INSTRUCTION B256_StoC   (* revision 1.0 20170916, vendor Kenneth A. Fischer *)
// Convert 256-bit value using 64 hex string characters into 256-bit value using 22 12-bit pieces
// Revision note:
// Rev1.0: 20170916 - Initial Release
VAR_IN_OUT
   Inp_S : STRING; {required}
   Out_C : DINT[22]; {required}
END_VAR
VAR
   byte : DINT[3];
   D_SHL : D_SHL;
   i : INT;
   j : INT;
   k : DINT;
   temp : DINT;
END_VAR

ROUTINE Logic   (* ladder *)
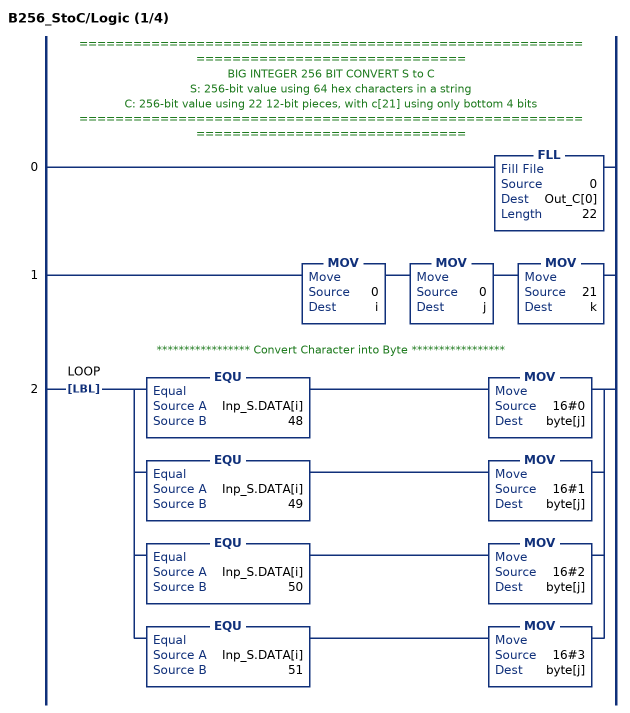
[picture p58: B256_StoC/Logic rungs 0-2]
   // ======================================================================================
   // BIG INTEGER 256 BIT CONVERT S to C
   // S: 256-bit value using 64 hex characters in a string
   // C: 256-bit value using 22 12-bit pieces, with c[21] using only bottom 4 bits
   // ======================================================================================
   0: FLL(0,Out_C[0],22);
   1: MOV(0,i)MOV(0,j)MOV(21,k);
   // ***************** Convert Character into Byte *****************
   2: LBL(LOOP)[EQU(Inp_S.DATA[i],48) MOV(16#0,byte[j]) ,EQU(Inp_S.DATA[i],49) MOV(16#1,byte[j]) ,EQU(Inp_S.DATA[i],50) MOV(16#2,byte[j]) ,EQU(Inp_S.DATA[i],51) MOV(16#3,byte[j]) ];
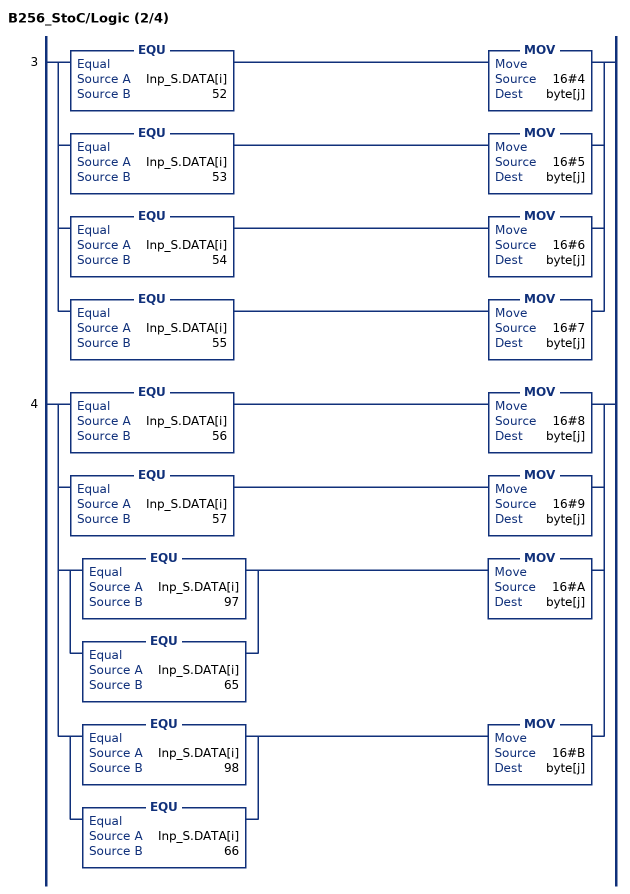
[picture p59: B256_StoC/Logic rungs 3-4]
   3: [EQU(Inp_S.DATA[i],52) MOV(16#4,byte[j]) ,EQU(Inp_S.DATA[i],53) MOV(16#5,byte[j]) ,EQU(Inp_S.DATA[i],54) MOV(16#6,byte[j]) ,EQU(Inp_S.DATA[i],55) MOV(16#7,byte[j]) ];
   4: [EQU(Inp_S.DATA[i],56) MOV(16#8,byte[j]) ,EQU(Inp_S.DATA[i],57) MOV(16#9,byte[j]) ,[EQU(Inp_S.DATA[i],97) ,EQU(Inp_S.DATA[i],65) ] MOV(16#A,byte[j]) ,[EQU(Inp_S.DATA[i],98) ,EQU(Inp_S.DATA[i],66) ] MOV(16#B,byte[j]) ];
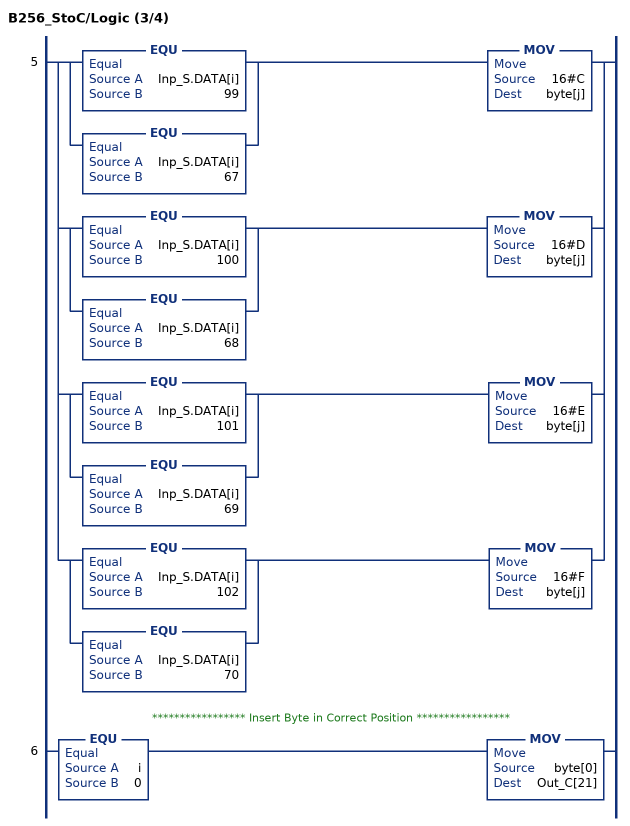
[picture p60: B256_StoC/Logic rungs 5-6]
   5: [[EQU(Inp_S.DATA[i],99) ,EQU(Inp_S.DATA[i],67) ] MOV(16#C,byte[j]) ,[EQU(Inp_S.DATA[i],100) ,EQU(Inp_S.DATA[i],68) ] MOV(16#D,byte[j]) ,[EQU(Inp_S.DATA[i],101) ,EQU(Inp_S.DATA[i],69) ] MOV(16#E,byte[j]) ,[EQU(Inp_S.DATA[i],102) ,EQU(Inp_S.DATA[i],70) ] MOV(16#F,byte[j]) ];
   // ***************** Insert Byte in Correct Position *****************
   6: EQU(i,0)MOV(byte[0],Out_C[21]);
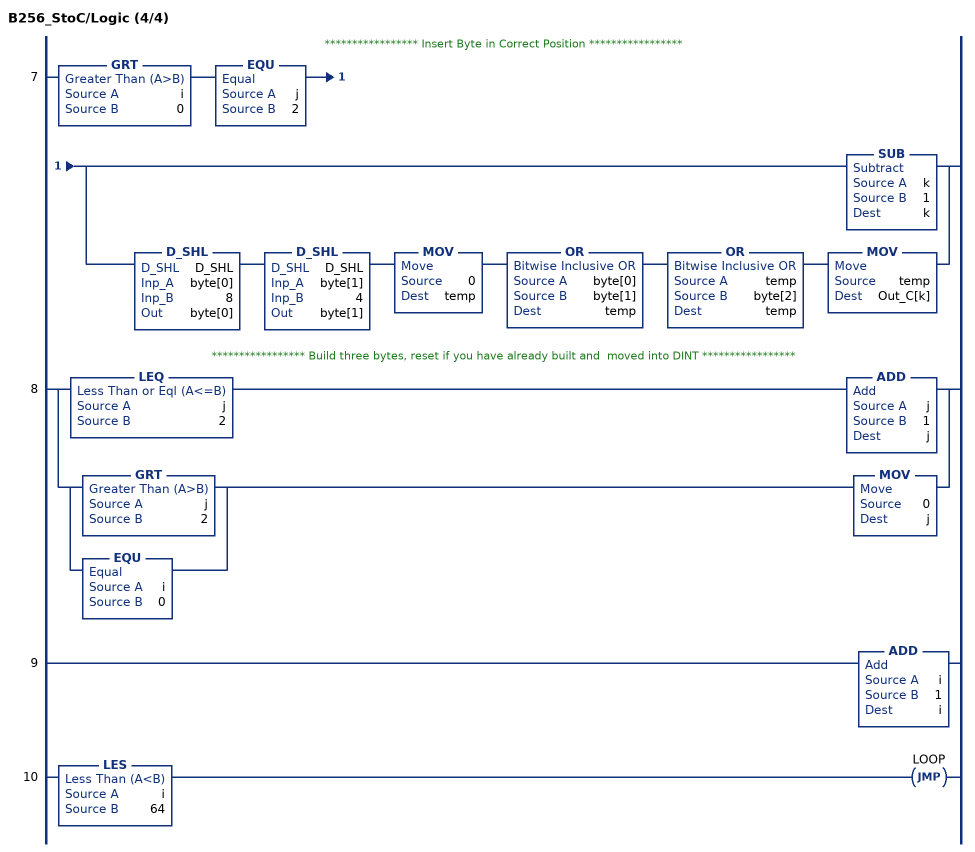
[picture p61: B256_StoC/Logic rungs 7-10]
   // ***************** Insert Byte in Correct Position *****************
   7: GRT(i,0)EQU(j,2)[SUB(k,1,k) ,D_SHL(D_SHL,byte[0],8,byte[0]) D_SHL(D_SHL,byte[1],4,byte[1]) MOV(0,temp) OR(byte[0],byte[1],temp) OR(temp,byte[2],temp) MOV(temp,Out_C[k]) ];
   // ***************** Build three bytes, reset if you have already built and  moved into DINT *****************
   8: [LEQ(j,2) ADD(j,1,j) ,[GRT(j,2) ,EQU(i,0) ] MOV(0,j) ];
   9: ADD(i,1,i);
   10: LES(i,64)JMP(LOOP);
END_ROUTINE
END_ADD_ON_INSTRUCTION

ADD_ON_INSTRUCTION B256_StoSLE   (* revision 1.0 20170916, vendor Kenneth A. Fischer *)
// Convert 256-bit big-endian string to a little-endian string
// Revision note:
// Rev1.0: 20170916 - Initial Release
VAR_IN_OUT
   In_S : STRING; {required}
   Out_S : STRING; {required}
END_VAR

ROUTINE Logic   (* ladder *)
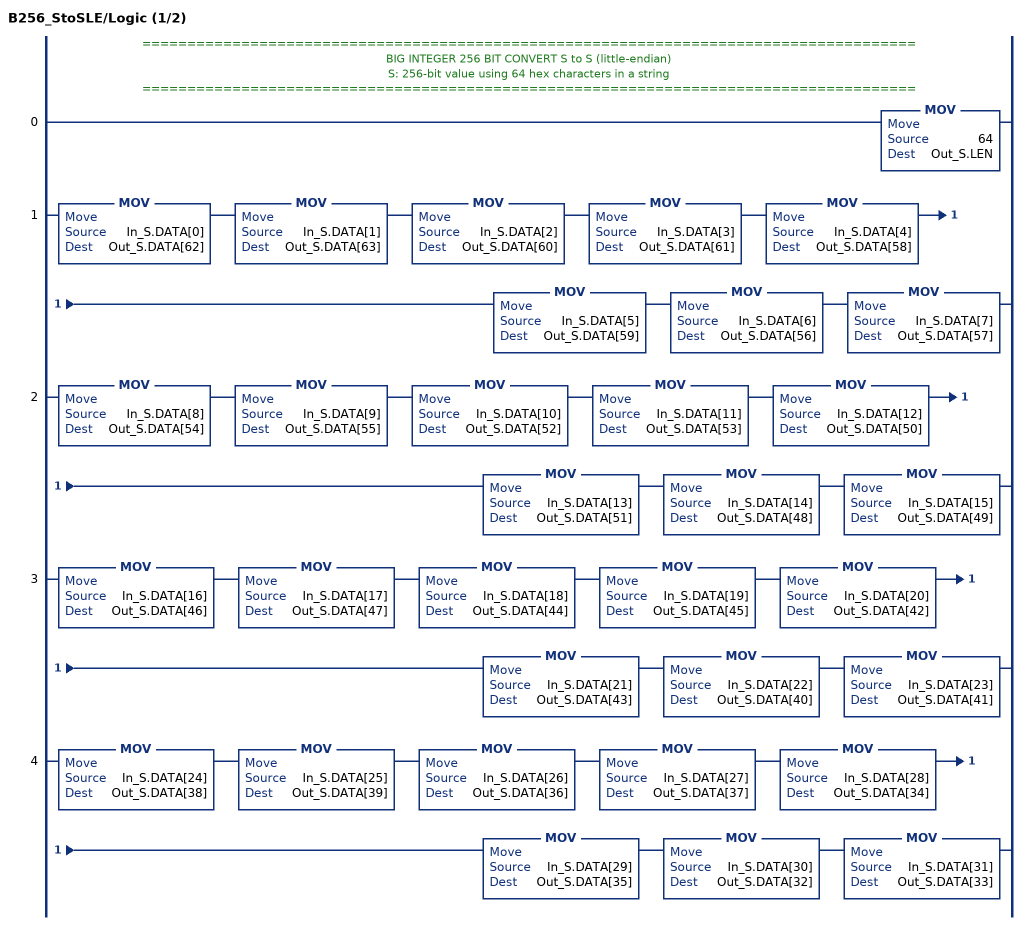
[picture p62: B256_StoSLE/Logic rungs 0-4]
   // ======================================================================================
   // BIG INTEGER 256 BIT CONVERT S to S (little-endian)
   // S: 256-bit value using 64 hex characters in a string
   // ======================================================================================
   0: MOV(64,Out_S.LEN);
   1: MOV(In_S.DATA[0],Out_S.DATA[62])MOV(In_S.DATA[1],Out_S.DATA[63])MOV(In_S.DATA[2],Out_S.DATA[60])MOV(In_S.DATA[3],Out_S.DATA[61])MOV(In_S.DATA[4],Out_S.DATA[58])MOV(In_S.DATA[5],Out_S.DATA[59])MOV(In_S.DATA[6],Out_S.DATA[56])MOV(In_S.DATA[7],Out_S.DATA[57]);
   2: MOV(In_S.DATA[8],Out_S.DATA[54])MOV(In_S.DATA[9],Out_S.DATA[55])MOV(In_S.DATA[10],Out_S.DATA[52])MOV(In_S.DATA[11],Out_S.DATA[53])MOV(In_S.DATA[12],Out_S.DATA[50])MOV(In_S.DATA[13],Out_S.DATA[51])MOV(In_S.DATA[14],Out_S.DATA[48])MOV(In_S.DATA[15],Out_S.DATA[49]);
   3: MOV(In_S.DATA[16],Out_S.DATA[46])MOV(In_S.DATA[17],Out_S.DATA[47])MOV(In_S.DATA[18],Out_S.DATA[44])MOV(In_S.DATA[19],Out_S.DATA[45])MOV(In_S.DATA[20],Out_S.DATA[42])MOV(In_S.DATA[21],Out_S.DATA[43])MOV(In_S.DATA[22],Out_S.DATA[40])MOV(In_S.DATA[23],Out_S.DATA[41]);
   4: MOV(In_S.DATA[24],Out_S.DATA[38])MOV(In_S.DATA[25],Out_S.DATA[39])MOV(In_S.DATA[26],Out_S.DATA[36])MOV(In_S.DATA[27],Out_S.DATA[37])MOV(In_S.DATA[28],Out_S.DATA[34])MOV(In_S.DATA[29],Out_S.DATA[35])MOV(In_S.DATA[30],Out_S.DATA[32])MOV(In_S.DATA[31],Out_S.DATA[33]);
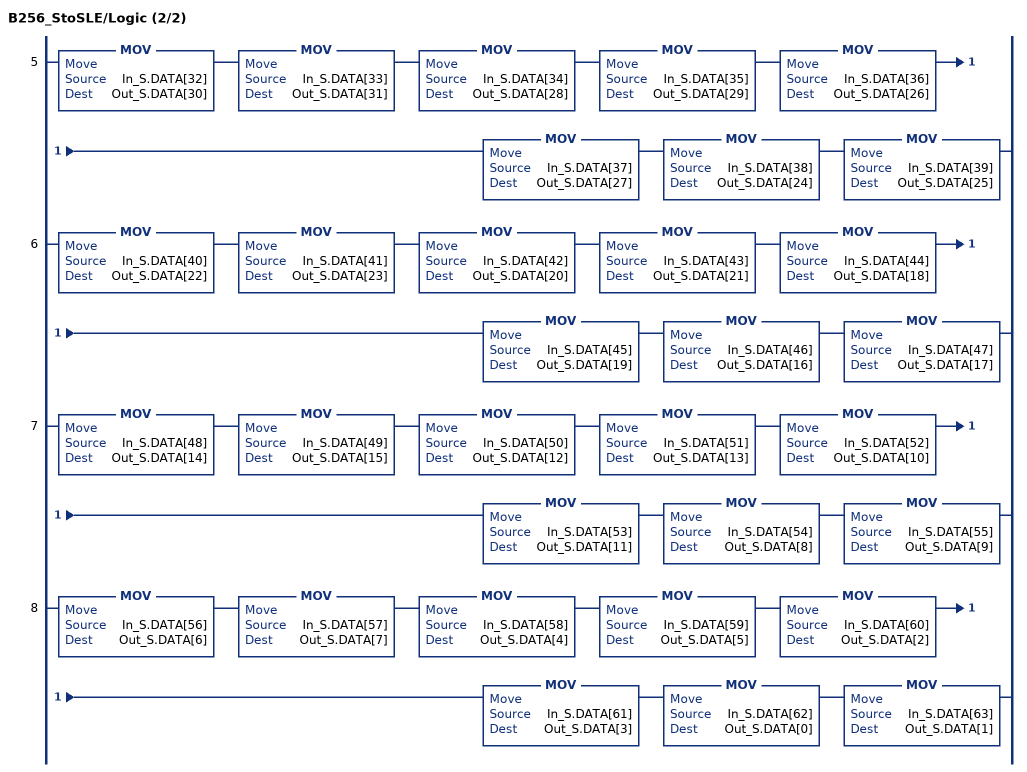
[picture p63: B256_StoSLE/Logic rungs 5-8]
   5: MOV(In_S.DATA[32],Out_S.DATA[30])MOV(In_S.DATA[33],Out_S.DATA[31])MOV(In_S.DATA[34],Out_S.DATA[28])MOV(In_S.DATA[35],Out_S.DATA[29])MOV(In_S.DATA[36],Out_S.DATA[26])MOV(In_S.DATA[37],Out_S.DATA[27])MOV(In_S.DATA[38],Out_S.DATA[24])MOV(In_S.DATA[39],Out_S.DATA[25]);
   6: MOV(In_S.DATA[40],Out_S.DATA[22])MOV(In_S.DATA[41],Out_S.DATA[23])MOV(In_S.DATA[42],Out_S.DATA[20])MOV(In_S.DATA[43],Out_S.DATA[21])MOV(In_S.DATA[44],Out_S.DATA[18])MOV(In_S.DATA[45],Out_S.DATA[19])MOV(In_S.DATA[46],Out_S.DATA[16])MOV(In_S.DATA[47],Out_S.DATA[17]);
   7: MOV(In_S.DATA[48],Out_S.DATA[14])MOV(In_S.DATA[49],Out_S.DATA[15])MOV(In_S.DATA[50],Out_S.DATA[12])MOV(In_S.DATA[51],Out_S.DATA[13])MOV(In_S.DATA[52],Out_S.DATA[10])MOV(In_S.DATA[53],Out_S.DATA[11])MOV(In_S.DATA[54],Out_S.DATA[8])MOV(In_S.DATA[55],Out_S.DATA[9]);
   8: MOV(In_S.DATA[56],Out_S.DATA[6])MOV(In_S.DATA[57],Out_S.DATA[7])MOV(In_S.DATA[58],Out_S.DATA[4])MOV(In_S.DATA[59],Out_S.DATA[5])MOV(In_S.DATA[60],Out_S.DATA[2])MOV(In_S.DATA[61],Out_S.DATA[3])MOV(In_S.DATA[62],Out_S.DATA[0])MOV(In_S.DATA[63],Out_S.DATA[1]);
END_ROUTINE
END_ADD_ON_INSTRUCTION

ADD_ON_INSTRUCTION B512_HtoD   (* revision 1.0 20170916, vendor Kenneth A. Fischer *)
// Takes a 512-bit hash value stored as 8 64-bit pieces and converts it to a 512-bit value stored as 42 12-bit pieces and 1 8-bit piece as the MSB
// Revision note:
// Rev1.0: 20170916 - Initial Release
VAR_IN_OUT
   Inp_H : LINT[8]; {required}
   Out_D : DINT[43]; {required}
END_VAR
VAR
   i : INT := 41;
   j : INT := 62;
   Wrk_InpL : DINT[16];
   D_SHR : D_SHR;
   TEMP1 : DINT;
   D_SHL : D_SHL;
   TEMP2 : DINT;
   EE : DINT[64];
END_VAR

ROUTINE Logic   (* ladder *)
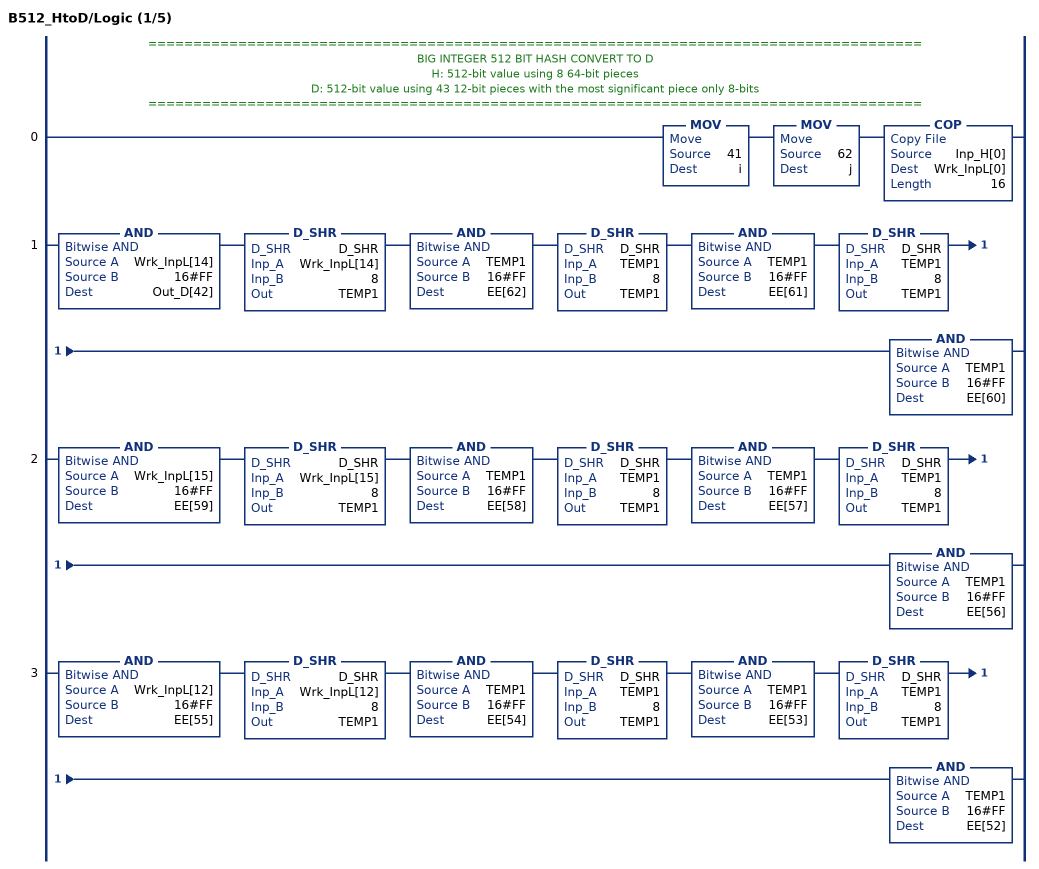
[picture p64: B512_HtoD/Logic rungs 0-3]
   // ======================================================================================
   // BIG INTEGER 512 BIT HASH CONVERT TO D
   // H: 512-bit value using 8 64-bit pieces
   // D: 512-bit value using 43 12-bit pieces with the most significant piece only 8-bits
   // ======================================================================================
   0: MOV(41,i)MOV(62,j)COP(Inp_H[0],Wrk_InpL[0],16);
   1: AND(Wrk_InpL[14],16#FF,Out_D[42])D_SHR(D_SHR,Wrk_InpL[14],8,TEMP1)AND(TEMP1,16#FF,EE[62])D_SHR(D_SHR,TEMP1,8,TEMP1)AND(TEMP1,16#FF,EE[61])D_SHR(D_SHR,TEMP1,8,TEMP1)AND(TEMP1,16#FF,EE[60]);
   2: AND(Wrk_InpL[15],16#FF,EE[59])D_SHR(D_SHR,Wrk_InpL[15],8,TEMP1)AND(TEMP1,16#FF,EE[58])D_SHR(D_SHR,TEMP1,8,TEMP1)AND(TEMP1,16#FF,EE[57])D_SHR(D_SHR,TEMP1,8,TEMP1)AND(TEMP1,16#FF,EE[56]);
   3: AND(Wrk_InpL[12],16#FF,EE[55])D_SHR(D_SHR,Wrk_InpL[12],8,TEMP1)AND(TEMP1,16#FF,EE[54])D_SHR(D_SHR,TEMP1,8,TEMP1)AND(TEMP1,16#FF,EE[53])D_SHR(D_SHR,TEMP1,8,TEMP1)AND(TEMP1,16#FF,EE[52]);
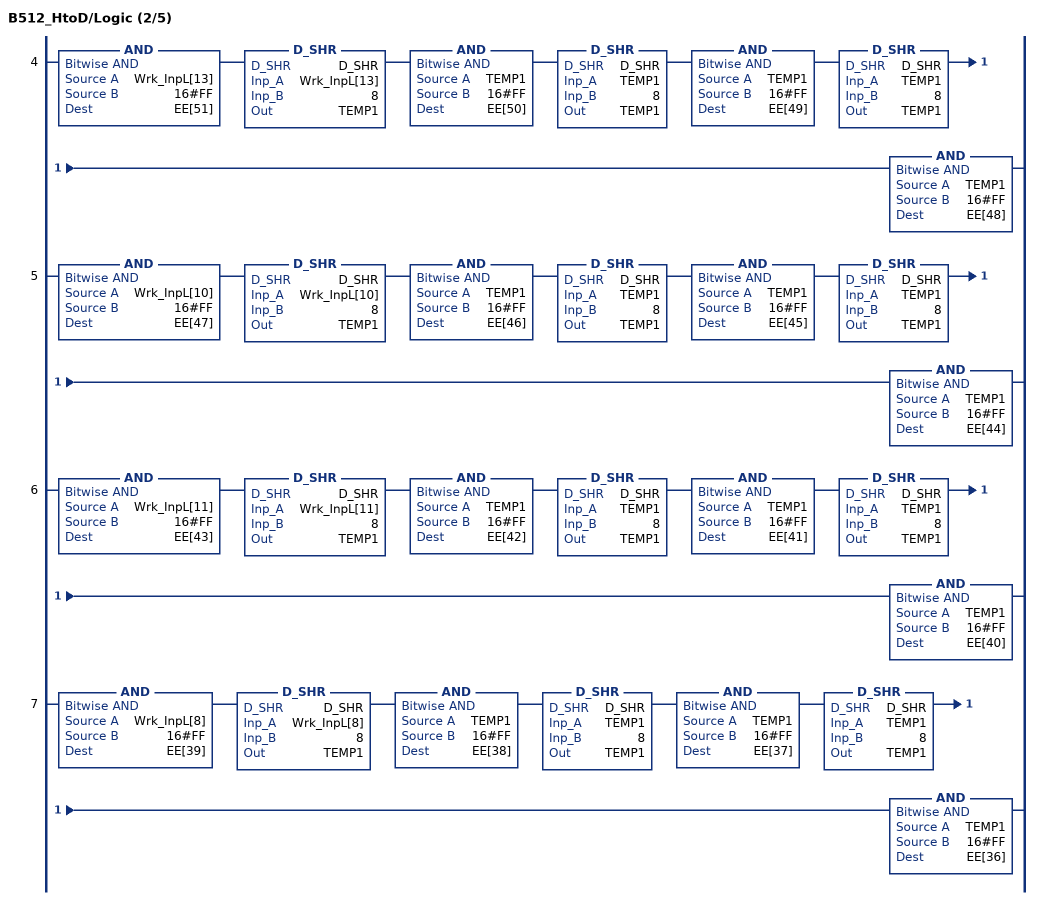
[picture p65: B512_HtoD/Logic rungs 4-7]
   4: AND(Wrk_InpL[13],16#FF,EE[51])D_SHR(D_SHR,Wrk_InpL[13],8,TEMP1)AND(TEMP1,16#FF,EE[50])D_SHR(D_SHR,TEMP1,8,TEMP1)AND(TEMP1,16#FF,EE[49])D_SHR(D_SHR,TEMP1,8,TEMP1)AND(TEMP1,16#FF,EE[48]);
   5: AND(Wrk_InpL[10],16#FF,EE[47])D_SHR(D_SHR,Wrk_InpL[10],8,TEMP1)AND(TEMP1,16#FF,EE[46])D_SHR(D_SHR,TEMP1,8,TEMP1)AND(TEMP1,16#FF,EE[45])D_SHR(D_SHR,TEMP1,8,TEMP1)AND(TEMP1,16#FF,EE[44]);
   6: AND(Wrk_InpL[11],16#FF,EE[43])D_SHR(D_SHR,Wrk_InpL[11],8,TEMP1)AND(TEMP1,16#FF,EE[42])D_SHR(D_SHR,TEMP1,8,TEMP1)AND(TEMP1,16#FF,EE[41])D_SHR(D_SHR,TEMP1,8,TEMP1)AND(TEMP1,16#FF,EE[40]);
   7: AND(Wrk_InpL[8],16#FF,EE[39])D_SHR(D_SHR,Wrk_InpL[8],8,TEMP1)AND(TEMP1,16#FF,EE[38])D_SHR(D_SHR,TEMP1,8,TEMP1)AND(TEMP1,16#FF,EE[37])D_SHR(D_SHR,TEMP1,8,TEMP1)AND(TEMP1,16#FF,EE[36]);
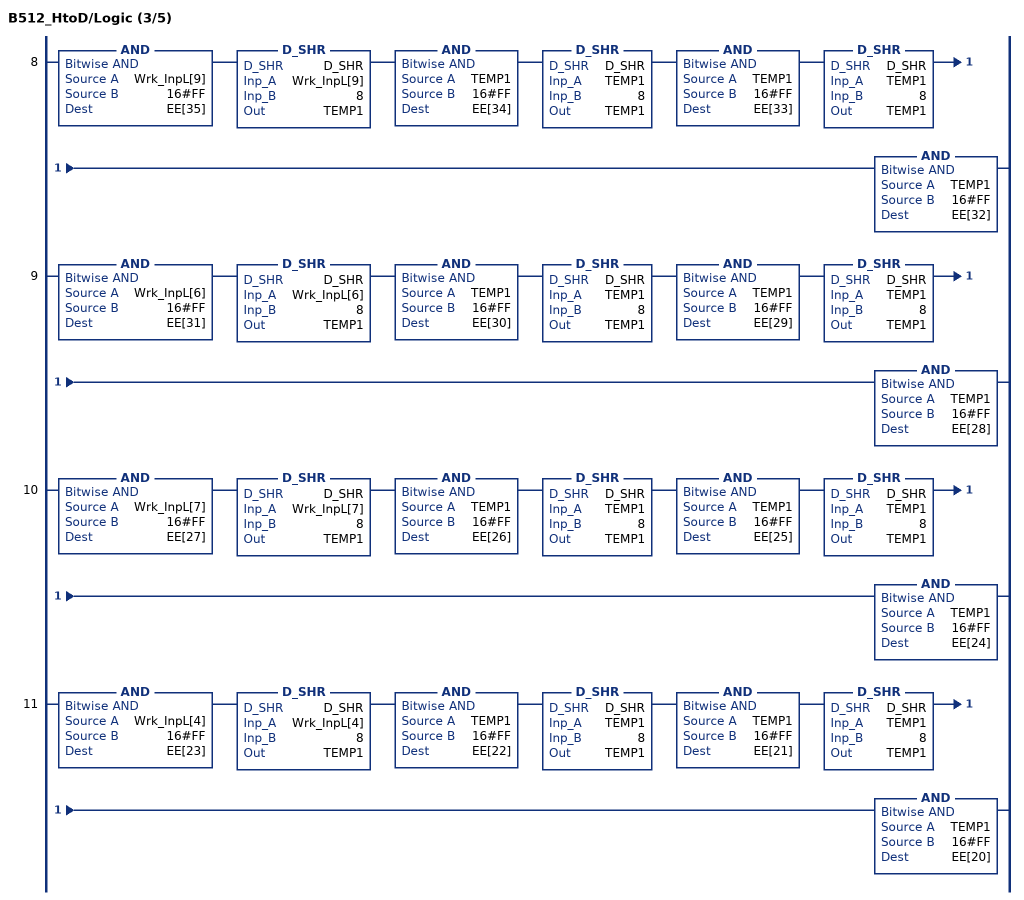
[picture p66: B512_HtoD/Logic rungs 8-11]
   8: AND(Wrk_InpL[9],16#FF,EE[35])D_SHR(D_SHR,Wrk_InpL[9],8,TEMP1)AND(TEMP1,16#FF,EE[34])D_SHR(D_SHR,TEMP1,8,TEMP1)AND(TEMP1,16#FF,EE[33])D_SHR(D_SHR,TEMP1,8,TEMP1)AND(TEMP1,16#FF,EE[32]);
   9: AND(Wrk_InpL[6],16#FF,EE[31])D_SHR(D_SHR,Wrk_InpL[6],8,TEMP1)AND(TEMP1,16#FF,EE[30])D_SHR(D_SHR,TEMP1,8,TEMP1)AND(TEMP1,16#FF,EE[29])D_SHR(D_SHR,TEMP1,8,TEMP1)AND(TEMP1,16#FF,EE[28]);
   10: AND(Wrk_InpL[7],16#FF,EE[27])D_SHR(D_SHR,Wrk_InpL[7],8,TEMP1)AND(TEMP1,16#FF,EE[26])D_SHR(D_SHR,TEMP1,8,TEMP1)AND(TEMP1,16#FF,EE[25])D_SHR(D_SHR,TEMP1,8,TEMP1)AND(TEMP1,16#FF,EE[24]);
   11: AND(Wrk_InpL[4],16#FF,EE[23])D_SHR(D_SHR,Wrk_InpL[4],8,TEMP1)AND(TEMP1,16#FF,EE[22])D_SHR(D_SHR,TEMP1,8,TEMP1)AND(TEMP1,16#FF,EE[21])D_SHR(D_SHR,TEMP1,8,TEMP1)AND(TEMP1,16#FF,EE[20]);
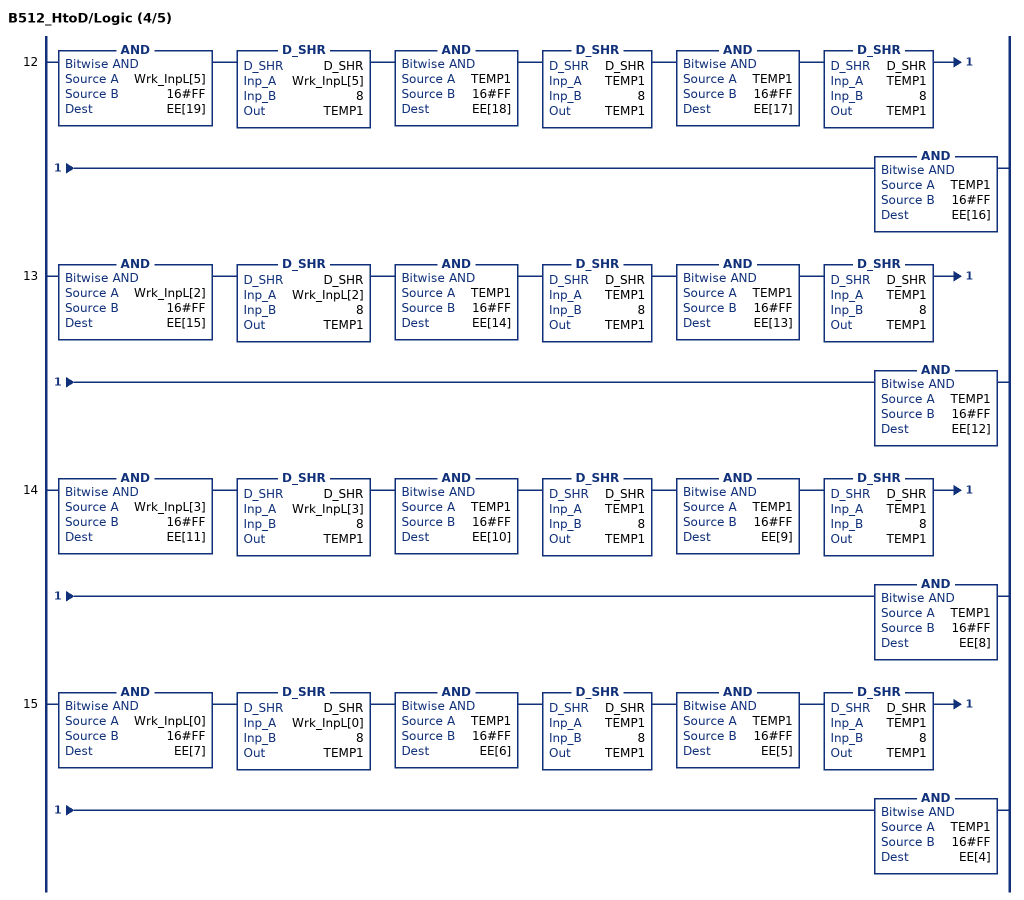
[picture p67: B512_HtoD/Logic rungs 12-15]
   12: AND(Wrk_InpL[5],16#FF,EE[19])D_SHR(D_SHR,Wrk_InpL[5],8,TEMP1)AND(TEMP1,16#FF,EE[18])D_SHR(D_SHR,TEMP1,8,TEMP1)AND(TEMP1,16#FF,EE[17])D_SHR(D_SHR,TEMP1,8,TEMP1)AND(TEMP1,16#FF,EE[16]);
   13: AND(Wrk_InpL[2],16#FF,EE[15])D_SHR(D_SHR,Wrk_InpL[2],8,TEMP1)AND(TEMP1,16#FF,EE[14])D_SHR(D_SHR,TEMP1,8,TEMP1)AND(TEMP1,16#FF,EE[13])D_SHR(D_SHR,TEMP1,8,TEMP1)AND(TEMP1,16#FF,EE[12]);
   14: AND(Wrk_InpL[3],16#FF,EE[11])D_SHR(D_SHR,Wrk_InpL[3],8,TEMP1)AND(TEMP1,16#FF,EE[10])D_SHR(D_SHR,TEMP1,8,TEMP1)AND(TEMP1,16#FF,EE[9])D_SHR(D_SHR,TEMP1,8,TEMP1)AND(TEMP1,16#FF,EE[8]);
   15: AND(Wrk_InpL[0],16#FF,EE[7])D_SHR(D_SHR,Wrk_InpL[0],8,TEMP1)AND(TEMP1,16#FF,EE[6])D_SHR(D_SHR,TEMP1,8,TEMP1)AND(TEMP1,16#FF,EE[5])D_SHR(D_SHR,TEMP1,8,TEMP1)AND(TEMP1,16#FF,EE[4]);
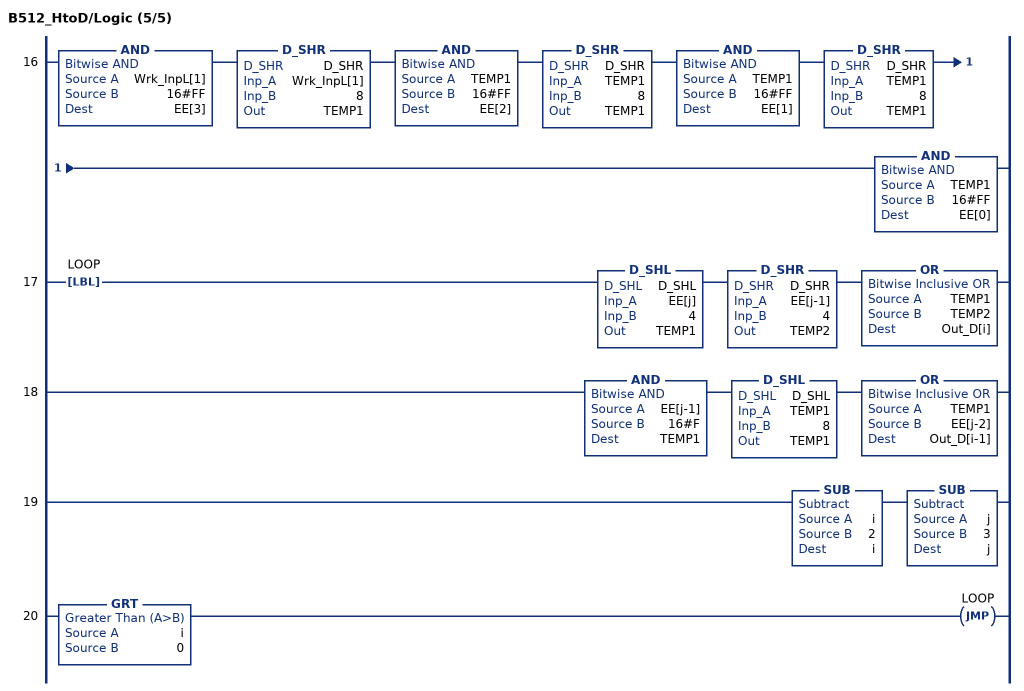
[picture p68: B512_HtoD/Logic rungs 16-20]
   16: AND(Wrk_InpL[1],16#FF,EE[3])D_SHR(D_SHR,Wrk_InpL[1],8,TEMP1)AND(TEMP1,16#FF,EE[2])D_SHR(D_SHR,TEMP1,8,TEMP1)AND(TEMP1,16#FF,EE[1])D_SHR(D_SHR,TEMP1,8,TEMP1)AND(TEMP1,16#FF,EE[0]);
   17: LBL(LOOP)D_SHL(D_SHL,EE[j],4,TEMP1)D_SHR(D_SHR,EE[j-1],4,TEMP2)OR(TEMP1,TEMP2,Out_D[i]);
   18: AND(EE[j-1],16#F,TEMP1)D_SHL(D_SHL,TEMP1,8,TEMP1)OR(TEMP1,EE[j-2],Out_D[i-1]);
   19: SUB(i,2,i)SUB(j,3,j);
   20: GRT(i,0)JMP(LOOP);
END_ROUTINE
END_ADD_ON_INSTRUCTION

ADD_ON_INSTRUCTION L_ADD   (* revision 1.0 00 Release, vendor Rockwell Automation *)
// Add (64-bit)
// Revision note:
// Initial Release
// Help:
// Adds two LINT (signed 64-bit) values and returns a LINT (signed 64-bit) sum.
// Also provides math status bits for Carry, Negative, Overflow and Zero result
// (equivalent to built-in S:C, S:N, S:V, S:Z).
VAR_IN_OUT
   Inp_A : LINT; {required}   // First Addend, 64-bit Integer
   Inp_B : LINT; {required}   // Second Addend, 64-bit Integer
   Out : LINT; {required}   // Sum, 64-bit Integer
END_VAR
VAR_OUTPUT
   Sts_C : BOOL; {access Read Only, visible}   // Carry result
   Sts_N : BOOL; {access Read Only, visible}   // Negative result
   Sts_V : BOOL; {access Read Only, visible}   // Overflow result
   Sts_Z : BOOL; {access Read Only, visible}   // Zero result
END_VAR
VAR
   Wrk_Sum : DINT[3];   // 20- and 24-bit fields of Out (sum)
   Wrk_B : DINT[3];   // 20- and 24-bit fields of Inp_B
   Wrk_A : DINT[3];   // 20- and 24-bit fields of Inp_A
   Wrk_Out : DINT[2];   // Output as two 32-bit DINTs
   Wrk_InpB : DINT[2];   // Input B as two 32-bit DINTs
   Wrk_InpA : DINT[2];   // Input A as two 32-bit DINTs
END_VAR

ROUTINE Logic   (* ladder *)
// Do 64-bit addition
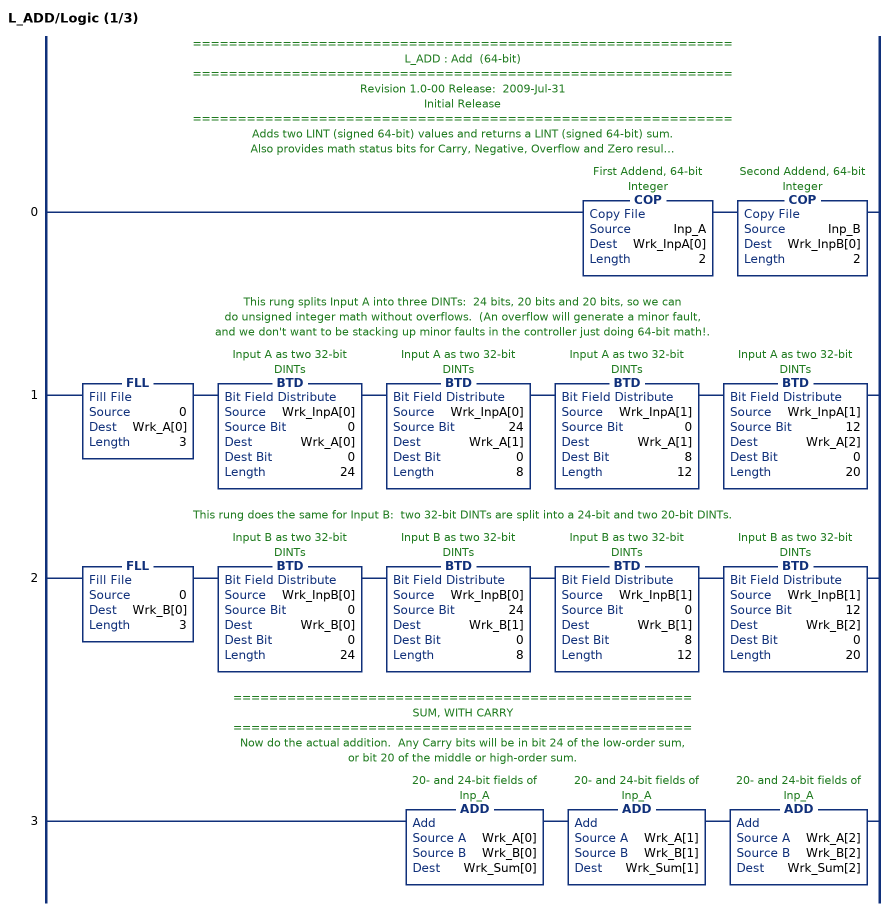
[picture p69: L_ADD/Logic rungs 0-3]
   // ============================================================
   // L_ADD : Add  (64-bit)
   // ============================================================
   // Revision 1.0-00 Release:  2009-Jul-31
   // Initial Release
   // ============================================================
   // Adds two LINT (signed 64-bit) values and returns a LINT (signed 64-bit) sum.
   // Also provides math status bits for Carry, Negative, Overflow and Zero result
   // (equivalent to built-in S:C, S:N, S:V, S:Z).
   // This instruction breaks the LINT addends into three DINTs
   // (24 bits, 20 bits and 20 bits) to do the math in order to
   // avoid generating a Controller MINOR FAULT on overflow.
   // (Sample code provided in RSLogix 5000 Online Help is much
   // smaller and faster, but causes numerous Minor Faults on
   // Overflows -- S:V -- on the low-order sum!  The controller must
   // take time to log the minor faults, and many users do not want to see
   // Minor Faults on normal math operations.  See the RSLogix 5000
   // Help Topic "Arithmetic Status Flags" for more information.)
   // ===================================================
   // CONVERT LINTs TO DINTs
   // ===================================================
   // These COPies take the input LINTs and break them into pairs of DINTs so we can do math on them.
   // Logix V17 has a LINT data type, but math instructions (and AOI Input and Output Parameters) don't support LINT.
   0: COP(Inp_A,Wrk_InpA[0],2)COP(Inp_B,Wrk_InpB[0],2);
   // This rung splits Input A into three DINTs:  24 bits, 20 bits and 20 bits, so we can
   // do unsigned integer math without overflows.  (An overflow will generate a minor fault,
   // and we don't want to be stacking up minor faults in the controller just doing 64-bit math!.
   1: FLL(0,Wrk_A[0],3)BTD(Wrk_InpA[0],0,Wrk_A[0],0,24)BTD(Wrk_InpA[0],24,Wrk_A[1],0,8)BTD(Wrk_InpA[1],0,Wrk_A[1],8,12)BTD(Wrk_InpA[1],12,Wrk_A[2],0,20);
   // This rung does the same for Input B:  two 32-bit DINTs are split into a 24-bit and two 20-bit DINTs.
   2: FLL(0,Wrk_B[0],3)BTD(Wrk_InpB[0],0,Wrk_B[0],0,24)BTD(Wrk_InpB[0],24,Wrk_B[1],0,8)BTD(Wrk_InpB[1],0,Wrk_B[1],8,12)BTD(Wrk_InpB[1],12,Wrk_B[2],0,20);
   // ===================================================
   // SUM, WITH CARRY
   // ===================================================
   // Now do the actual addition.  Any Carry bits will be in bit 24 of the low-order sum,
   // or bit 20 of the middle or high-order sum.
   3: ADD(Wrk_A[0],Wrk_B[0],Wrk_Sum[0])ADD(Wrk_A[1],Wrk_B[1],Wrk_Sum[1])ADD(Wrk_A[2],Wrk_B[2],Wrk_Sum[2]);
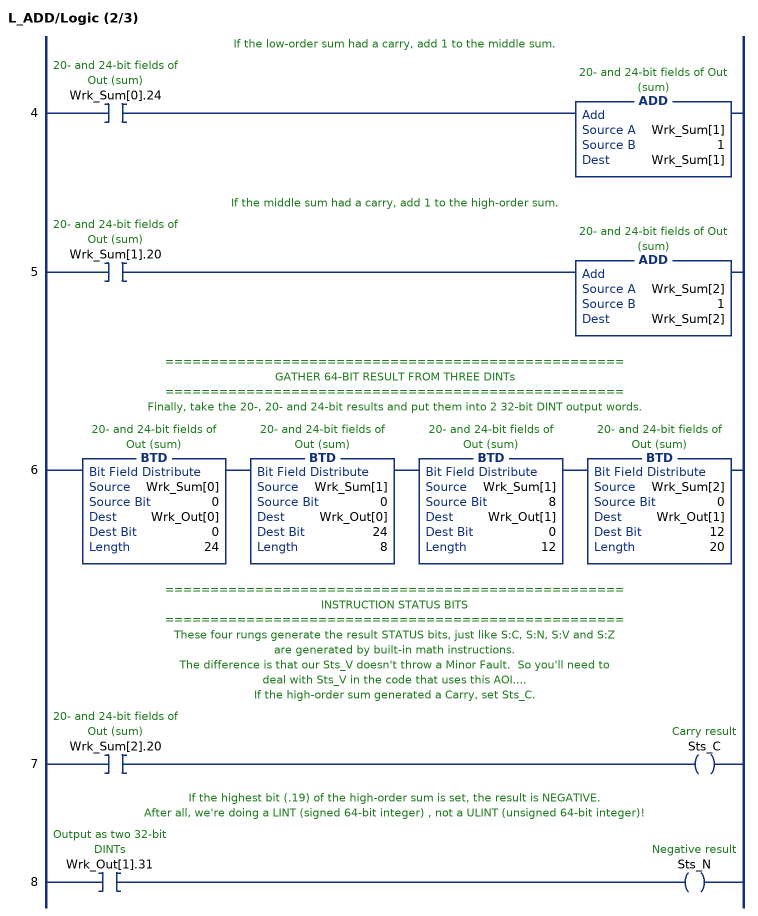
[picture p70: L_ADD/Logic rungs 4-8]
   // If the low-order sum had a carry, add 1 to the middle sum.
   4: XIC(Wrk_Sum[0].24)ADD(Wrk_Sum[1],1,Wrk_Sum[1]);
   // If the middle sum had a carry, add 1 to the high-order sum.
   5: XIC(Wrk_Sum[1].20)ADD(Wrk_Sum[2],1,Wrk_Sum[2]);
   // ===================================================
   // GATHER 64-BIT RESULT FROM THREE DINTs
   // ===================================================
   // Finally, take the 20-, 20- and 24-bit results and put them into 2 32-bit DINT output words.
   6: BTD(Wrk_Sum[0],0,Wrk_Out[0],0,24)BTD(Wrk_Sum[1],0,Wrk_Out[0],24,8)BTD(Wrk_Sum[1],8,Wrk_Out[1],0,12)BTD(Wrk_Sum[2],0,Wrk_Out[1],12,20);
   // ===================================================
   // INSTRUCTION STATUS BITS
   // ===================================================
   // These four rungs generate the result STATUS bits, just like S:C, S:N, S:V and S:Z
   // are generated by built-in math instructions.
   // The difference is that our Sts_V doesn't throw a Minor Fault.  So you'll need to
   // deal with Sts_V in the code that uses this AOI....
   // If the high-order sum generated a Carry, set Sts_C.
   7: XIC(Wrk_Sum[2].20)OTE(Sts_C);
   // If the highest bit (.19) of the high-order sum is set, the result is NEGATIVE.
   // After all, we're doing a LINT (signed 64-bit integer) , not a ULINT (unsigned 64-bit integer)!
   8: XIC(Wrk_Out[1].31)OTE(Sts_N);
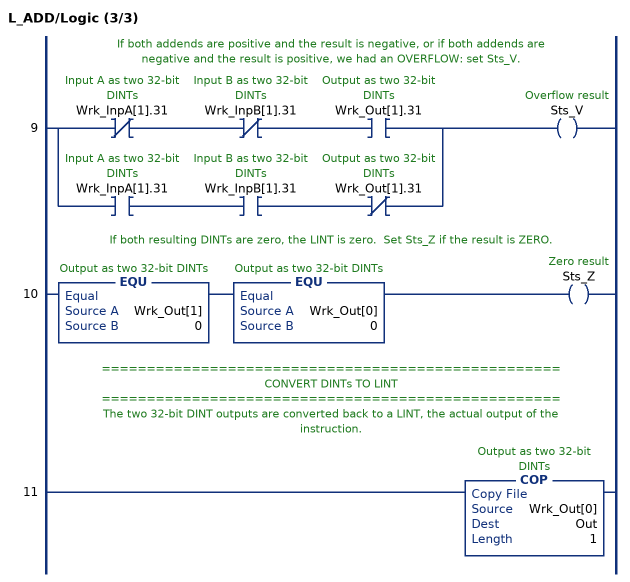
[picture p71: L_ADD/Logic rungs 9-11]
   // If both addends are positive and the result is negative, or if both addends are
   // negative and the result is positive, we had an OVERFLOW: set Sts_V.
   9: [XIO(Wrk_InpA[1].31) XIO(Wrk_InpB[1].31) XIC(Wrk_Out[1].31) ,XIC(Wrk_InpA[1].31) XIC(Wrk_InpB[1].31) XIO(Wrk_Out[1].31) ]OTE(Sts_V);
   // If both resulting DINTs are zero, the LINT is zero.  Set Sts_Z if the result is ZERO.
   10: EQU(Wrk_Out[1],0)EQU(Wrk_Out[0],0)OTE(Sts_Z);
   // ===================================================
   // CONVERT DINTs TO LINT
   // ===================================================
   // The two 32-bit DINT outputs are converted back to a LINT, the actual output of the instruction.
   11: COP(Wrk_Out[0],Out,1);
END_ROUTINE
END_ADD_ON_INSTRUCTION

ADD_ON_INSTRUCTION L_AND   (* revision 1.0 00 Release, vendor Rockwell Automation *)
// Bitwise AND (64-bit)
// Revision note:
// Initial Release
// Help:
// This instruction returns the bitwise Logical AND (output bit true if both corresponding
// input bits true) of two input 64-bit integers (LINTs), into an output 64-bit integer.
VAR_IN_OUT
   Inp_A : LINT; {required}   // Input A
   Inp_B : LINT; {required}   // Input B
   Out : LINT; {required}   // Output = Input A & Input B
END_VAR
VAR
   Wrk_Out : DINT[2];   // Output as two 32-bit DINTs
   Wrk_InpB : DINT[2];   // Input B as two 32-bit DINTs
   Wrk_InpA : DINT[2];   // Input A as two 32-bit DINTs
END_VAR

ROUTINE Logic   (* ladder *)
// Perform 64-bit bitwise logical AND
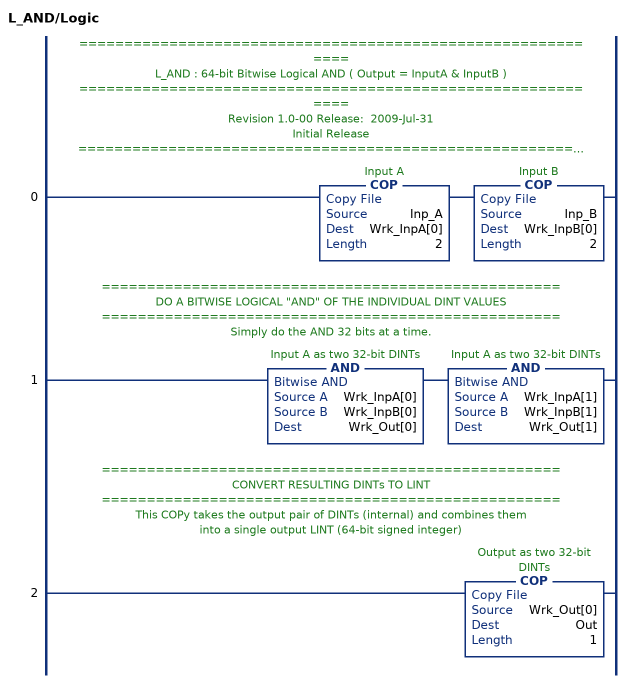
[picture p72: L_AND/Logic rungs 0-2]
   // ============================================================
   // L_AND : 64-bit Bitwise Logical AND ( Output = InputA & InputB )
   // ============================================================
   // Revision 1.0-00 Release:  2009-Jul-31
   // Initial Release
   // ============================================================
   // Returns the bitwise Logical AND of the input 64-bit integer (LINT) values.
   // This rung breaks each LINT input into two DINTs
   // (32-bit signed each) to do the logical AND function.
   // ===================================================
   // CONVERT LINTs TO DINTs
   // ===================================================
   // These COPies take the input LINT values and break them into a pair of DINTs each.
   0: COP(Inp_A,Wrk_InpA[0],2)COP(Inp_B,Wrk_InpB[0],2);
   // ===================================================
   // DO A BITWISE LOGICAL "AND" OF THE INDIVIDUAL DINT VALUES
   // ===================================================
   // Simply do the AND 32 bits at a time.
   1: AND(Wrk_InpA[0],Wrk_InpB[0],Wrk_Out[0])AND(Wrk_InpA[1],Wrk_InpB[1],Wrk_Out[1]);
   // ===================================================
   // CONVERT RESULTING DINTs TO LINT
   // ===================================================
   // This COPy takes the output pair of DINTs (internal) and combines them
   // into a single output LINT (64-bit signed integer)
   2: COP(Wrk_Out[0],Out,1);
END_ROUTINE
END_ADD_ON_INSTRUCTION
